VERSION 5.7 ;
  NOWIREEXTENSIONATPIN ON ;
  DIVIDERCHAR "/" ;
  BUSBITCHARS "[]" ;
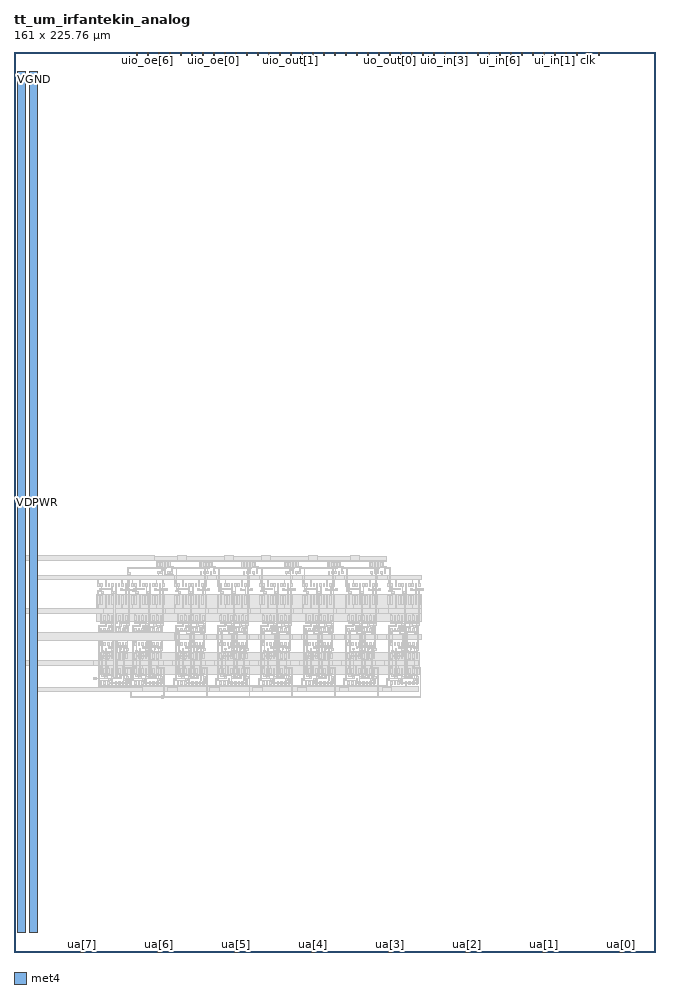
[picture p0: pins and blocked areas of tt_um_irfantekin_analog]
MACRO tt_um_irfantekin_analog
  CLASS BLOCK ;
  FOREIGN tt_um_irfantekin_analog ;
  ORIGIN 0.000 0.000 ;
  SIZE 161.000 BY 225.760 ;
  PIN clk
    DIRECTION INPUT ;
    USE SIGNAL ;
    PORT
      LAYER met4 ;
        RECT 143.830 224.760 144.130 225.760 ;
    END
  END clk
  PIN ena
    DIRECTION INPUT ;
    USE SIGNAL ;
    PORT
      LAYER met4 ;
        RECT 146.590 224.760 146.890 225.760 ;
    END
  END ena
  PIN rst_n
    DIRECTION INPUT ;
    USE SIGNAL ;
    PORT
      LAYER met4 ;
        RECT 141.070 224.760 141.370 225.760 ;
    END
  END rst_n
  PIN ua[0]
    DIRECTION INOUT ;
    USE SIGNAL ;
    PORT
      LAYER met4 ;
        RECT 151.810 0.000 152.710 1.000 ;
    END
  END ua[0]
  PIN ua[1]
    DIRECTION INOUT ;
    USE SIGNAL ;
    PORT
      LAYER met4 ;
        RECT 132.490 0.000 133.390 1.000 ;
    END
  END ua[1]
  PIN ua[2]
    DIRECTION INOUT ;
    USE SIGNAL ;
    PORT
      LAYER met4 ;
        RECT 113.170 0.000 114.070 1.000 ;
    END
  END ua[2]
  PIN ua[3]
    DIRECTION INOUT ;
    USE SIGNAL ;
    PORT
      LAYER met4 ;
        RECT 93.850 0.000 94.750 1.000 ;
    END
  END ua[3]
  PIN ua[4]
    DIRECTION INOUT ;
    USE SIGNAL ;
    PORT
      LAYER met4 ;
        RECT 74.530 0.000 75.430 1.000 ;
    END
  END ua[4]
  PIN ua[5]
    DIRECTION INOUT ;
    USE SIGNAL ;
    PORT
      LAYER met4 ;
        RECT 55.210 0.000 56.110 1.000 ;
    END
  END ua[5]
  PIN ua[6]
    DIRECTION INOUT ;
    USE SIGNAL ;
    PORT
      LAYER met4 ;
        RECT 35.890 0.000 36.790 1.000 ;
    END
  END ua[6]
  PIN ua[7]
    DIRECTION INOUT ;
    USE SIGNAL ;
    PORT
      LAYER met4 ;
        RECT 16.570 0.000 17.470 1.000 ;
    END
  END ua[7]
  PIN ui_in[0]
    DIRECTION INPUT ;
    USE SIGNAL ;
    PORT
      LAYER met4 ;
        RECT 138.310 224.760 138.610 225.760 ;
    END
  END ui_in[0]
  PIN ui_in[1]
    DIRECTION INPUT ;
    USE SIGNAL ;
    PORT
      LAYER met4 ;
        RECT 135.550 224.760 135.850 225.760 ;
    END
  END ui_in[1]
  PIN ui_in[2]
    DIRECTION INPUT ;
    USE SIGNAL ;
    PORT
      LAYER met4 ;
        RECT 132.790 224.760 133.090 225.760 ;
    END
  END ui_in[2]
  PIN ui_in[3]
    DIRECTION INPUT ;
    USE SIGNAL ;
    PORT
      LAYER met4 ;
        RECT 130.030 224.760 130.330 225.760 ;
    END
  END ui_in[3]
  PIN ui_in[4]
    DIRECTION INPUT ;
    USE SIGNAL ;
    PORT
      LAYER met4 ;
        RECT 127.270 224.760 127.570 225.760 ;
    END
  END ui_in[4]
  PIN ui_in[5]
    DIRECTION INPUT ;
    USE SIGNAL ;
    PORT
      LAYER met4 ;
        RECT 124.510 224.760 124.810 225.760 ;
    END
  END ui_in[5]
  PIN ui_in[6]
    DIRECTION INPUT ;
    USE SIGNAL ;
    PORT
      LAYER met4 ;
        RECT 121.750 224.760 122.050 225.760 ;
    END
  END ui_in[6]
  PIN ui_in[7]
    DIRECTION INPUT ;
    USE SIGNAL ;
    PORT
      LAYER met4 ;
        RECT 118.990 224.760 119.290 225.760 ;
    END
  END ui_in[7]
  PIN uio_in[0]
    DIRECTION INPUT ;
    USE SIGNAL ;
    PORT
      LAYER met4 ;
        RECT 116.230 224.760 116.530 225.760 ;
    END
  END uio_in[0]
  PIN uio_in[1]
    DIRECTION INPUT ;
    USE SIGNAL ;
    PORT
      LAYER met4 ;
        RECT 113.470 224.760 113.770 225.760 ;
    END
  END uio_in[1]
  PIN uio_in[2]
    DIRECTION INPUT ;
    USE SIGNAL ;
    PORT
      LAYER met4 ;
        RECT 110.710 224.760 111.010 225.760 ;
    END
  END uio_in[2]
  PIN uio_in[3]
    DIRECTION INPUT ;
    USE SIGNAL ;
    PORT
      LAYER met4 ;
        RECT 107.950 224.760 108.250 225.760 ;
    END
  END uio_in[3]
  PIN uio_in[4]
    DIRECTION INPUT ;
    USE SIGNAL ;
    PORT
      LAYER met4 ;
        RECT 105.190 224.760 105.490 225.760 ;
    END
  END uio_in[4]
  PIN uio_in[5]
    DIRECTION INPUT ;
    USE SIGNAL ;
    PORT
      LAYER met4 ;
        RECT 102.430 224.760 102.730 225.760 ;
    END
  END uio_in[5]
  PIN uio_in[6]
    DIRECTION INPUT ;
    USE SIGNAL ;
    PORT
      LAYER met4 ;
        RECT 99.670 224.760 99.970 225.760 ;
    END
  END uio_in[6]
  PIN uio_in[7]
    DIRECTION INPUT ;
    USE SIGNAL ;
    PORT
      LAYER met4 ;
        RECT 96.910 224.760 97.210 225.760 ;
    END
  END uio_in[7]
  PIN uio_oe[0]
    DIRECTION OUTPUT ;
    USE SIGNAL ;
    PORT
      LAYER met4 ;
        RECT 49.990 224.760 50.290 225.760 ;
    END
  END uio_oe[0]
  PIN uio_oe[1]
    DIRECTION OUTPUT ;
    USE SIGNAL ;
    PORT
      LAYER met4 ;
        RECT 47.230 224.760 47.530 225.760 ;
    END
  END uio_oe[1]
  PIN uio_oe[2]
    DIRECTION OUTPUT ;
    USE SIGNAL ;
    PORT
      LAYER met4 ;
        RECT 44.470 224.760 44.770 225.760 ;
    END
  END uio_oe[2]
  PIN uio_oe[3]
    DIRECTION OUTPUT ;
    USE SIGNAL ;
    PORT
      LAYER met4 ;
        RECT 41.710 224.760 42.010 225.760 ;
    END
  END uio_oe[3]
  PIN uio_oe[4]
    DIRECTION OUTPUT ;
    USE SIGNAL ;
    PORT
      LAYER met4 ;
        RECT 38.950 224.760 39.250 225.760 ;
    END
  END uio_oe[4]
  PIN uio_oe[5]
    DIRECTION OUTPUT ;
    USE SIGNAL ;
    PORT
      LAYER met4 ;
        RECT 36.190 224.760 36.490 225.760 ;
    END
  END uio_oe[5]
  PIN uio_oe[6]
    DIRECTION OUTPUT ;
    USE SIGNAL ;
    PORT
      LAYER met4 ;
        RECT 33.430 224.760 33.730 225.760 ;
    END
  END uio_oe[6]
  PIN uio_oe[7]
    DIRECTION OUTPUT ;
    USE SIGNAL ;
    PORT
      LAYER met4 ;
        RECT 30.670 224.760 30.970 225.760 ;
    END
  END uio_oe[7]
  PIN uio_out[0]
    DIRECTION OUTPUT ;
    USE SIGNAL ;
    PORT
      LAYER met4 ;
        RECT 72.070 224.760 72.370 225.760 ;
    END
  END uio_out[0]
  PIN uio_out[1]
    DIRECTION OUTPUT ;
    USE SIGNAL ;
    PORT
      LAYER met4 ;
        RECT 69.310 224.760 69.610 225.760 ;
    END
  END uio_out[1]
  PIN uio_out[2]
    DIRECTION OUTPUT ;
    USE SIGNAL ;
    PORT
      LAYER met4 ;
        RECT 66.550 224.760 66.850 225.760 ;
    END
  END uio_out[2]
  PIN uio_out[3]
    DIRECTION OUTPUT ;
    USE SIGNAL ;
    PORT
      LAYER met4 ;
        RECT 63.790 224.760 64.090 225.760 ;
    END
  END uio_out[3]
  PIN uio_out[4]
    DIRECTION OUTPUT ;
    USE SIGNAL ;
    PORT
      LAYER met4 ;
        RECT 61.030 224.760 61.330 225.760 ;
    END
  END uio_out[4]
  PIN uio_out[5]
    DIRECTION OUTPUT ;
    USE SIGNAL ;
    PORT
      LAYER met4 ;
        RECT 58.270 224.760 58.570 225.760 ;
    END
  END uio_out[5]
  PIN uio_out[6]
    DIRECTION OUTPUT ;
    USE SIGNAL ;
    PORT
      LAYER met4 ;
        RECT 55.510 224.760 55.810 225.760 ;
    END
  END uio_out[6]
  PIN uio_out[7]
    DIRECTION OUTPUT ;
    USE SIGNAL ;
    PORT
      LAYER met4 ;
        RECT 52.750 224.760 53.050 225.760 ;
    END
  END uio_out[7]
  PIN uo_out[0]
    DIRECTION OUTPUT ;
    USE SIGNAL ;
    PORT
      LAYER met4 ;
        RECT 94.150 224.760 94.450 225.760 ;
    END
  END uo_out[0]
  PIN uo_out[1]
    DIRECTION OUTPUT ;
    USE SIGNAL ;
    PORT
      LAYER met4 ;
        RECT 91.390 224.760 91.690 225.760 ;
    END
  END uo_out[1]
  PIN uo_out[2]
    DIRECTION OUTPUT ;
    USE SIGNAL ;
    PORT
      LAYER met4 ;
        RECT 88.630 224.760 88.930 225.760 ;
    END
  END uo_out[2]
  PIN uo_out[3]
    DIRECTION OUTPUT ;
    USE SIGNAL ;
    PORT
      LAYER met4 ;
        RECT 85.870 224.760 86.170 225.760 ;
    END
  END uo_out[3]
  PIN uo_out[4]
    DIRECTION OUTPUT ;
    USE SIGNAL ;
    PORT
      LAYER met4 ;
        RECT 83.110 224.760 83.410 225.760 ;
    END
  END uo_out[4]
  PIN uo_out[5]
    DIRECTION OUTPUT ;
    USE SIGNAL ;
    PORT
      LAYER met4 ;
        RECT 80.350 224.760 80.650 225.760 ;
    END
  END uo_out[5]
  PIN uo_out[6]
    DIRECTION OUTPUT ;
    USE SIGNAL ;
    PORT
      LAYER met4 ;
        RECT 77.590 224.760 77.890 225.760 ;
    END
  END uo_out[6]
  PIN uo_out[7]
    DIRECTION OUTPUT ;
    USE SIGNAL ;
    PORT
      LAYER met4 ;
        RECT 74.830 224.760 75.130 225.760 ;
    END
  END uo_out[7]
  PIN VDPWR
    DIRECTION INOUT ;
    USE POWER ;
    PORT
      LAYER met4 ;
        RECT 1.000 5.000 3.000 220.760 ;
    END
  END VDPWR
  PIN VGND
    DIRECTION INOUT ;
    USE GROUND ;
    PORT
      LAYER met4 ;
        RECT 4.000 5.000 6.000 220.760 ;
    END
  END VGND
  OBS
      LAYER nwell ;
        RECT 35.750 98.000 93.350 99.300 ;
        RECT 35.750 96.500 39.150 98.000 ;
        RECT 46.450 96.500 49.850 98.000 ;
        RECT 57.150 96.500 60.550 98.000 ;
        RECT 67.850 96.500 71.250 98.000 ;
        RECT 78.550 96.500 81.950 98.000 ;
        RECT 89.250 96.500 92.650 98.000 ;
        RECT 20.650 82.800 102.150 89.700 ;
        RECT 21.150 69.600 101.650 75.200 ;
      LAYER li1 ;
        RECT 32.650 99.300 34.950 99.400 ;
        RECT 41.050 99.300 43.350 99.400 ;
        RECT 52.750 99.300 55.050 99.400 ;
        RECT 62.150 99.300 64.450 99.400 ;
        RECT 73.950 99.300 76.250 99.400 ;
        RECT 84.450 99.300 86.750 99.400 ;
        RECT 31.950 98.200 93.350 99.300 ;
        RECT 36.150 97.800 36.350 98.200 ;
        RECT 37.750 97.800 37.950 98.200 ;
        RECT 46.850 97.800 47.050 98.200 ;
        RECT 48.450 97.800 48.650 98.200 ;
        RECT 57.550 97.800 57.750 98.200 ;
        RECT 59.150 97.800 59.350 98.200 ;
        RECT 68.250 97.800 68.450 98.200 ;
        RECT 69.850 97.800 70.050 98.200 ;
        RECT 78.950 97.800 79.150 98.200 ;
        RECT 80.550 97.800 80.750 98.200 ;
        RECT 89.650 97.800 89.850 98.200 ;
        RECT 91.250 97.800 91.450 98.200 ;
        RECT 36.050 96.800 36.450 97.800 ;
        RECT 36.850 96.800 37.250 97.800 ;
        RECT 37.650 96.800 38.050 97.800 ;
        RECT 38.450 96.800 38.850 97.800 ;
        RECT 46.750 96.800 47.150 97.800 ;
        RECT 47.550 96.800 47.950 97.800 ;
        RECT 48.350 96.800 48.750 97.800 ;
        RECT 49.150 96.800 49.550 97.800 ;
        RECT 57.450 96.800 57.850 97.800 ;
        RECT 58.250 96.800 58.650 97.800 ;
        RECT 59.050 96.800 59.450 97.800 ;
        RECT 59.850 96.800 60.250 97.800 ;
        RECT 68.150 96.800 68.550 97.800 ;
        RECT 68.950 96.800 69.350 97.800 ;
        RECT 69.750 96.800 70.150 97.800 ;
        RECT 70.550 96.800 70.950 97.800 ;
        RECT 78.850 96.800 79.250 97.800 ;
        RECT 79.650 96.800 80.050 97.800 ;
        RECT 80.450 96.800 80.850 97.800 ;
        RECT 81.250 96.800 81.650 97.800 ;
        RECT 89.550 96.800 89.950 97.800 ;
        RECT 90.350 96.800 90.750 97.800 ;
        RECT 91.150 96.800 91.550 97.800 ;
        RECT 91.950 96.800 92.350 97.800 ;
        RECT 36.250 96.100 36.650 96.500 ;
        RECT 36.950 96.400 37.150 96.800 ;
        RECT 38.550 96.600 38.750 96.800 ;
        RECT 37.850 96.400 38.250 96.500 ;
        RECT 38.550 96.400 39.950 96.600 ;
        RECT 36.950 96.200 38.250 96.400 ;
        RECT 37.750 96.100 38.250 96.200 ;
        RECT 39.450 96.100 39.950 96.400 ;
        RECT 46.950 96.100 47.350 96.500 ;
        RECT 47.650 96.400 47.850 96.800 ;
        RECT 49.250 96.600 49.450 96.800 ;
        RECT 48.550 96.400 48.950 96.500 ;
        RECT 49.250 96.400 50.650 96.600 ;
        RECT 47.650 96.200 48.950 96.400 ;
        RECT 48.450 96.100 48.950 96.200 ;
        RECT 50.150 96.100 50.650 96.400 ;
        RECT 57.650 96.100 58.050 96.500 ;
        RECT 58.350 96.400 58.550 96.800 ;
        RECT 59.950 96.600 60.150 96.800 ;
        RECT 59.250 96.400 59.650 96.500 ;
        RECT 59.950 96.400 61.350 96.600 ;
        RECT 58.350 96.200 59.650 96.400 ;
        RECT 59.150 96.100 59.650 96.200 ;
        RECT 60.850 96.100 61.350 96.400 ;
        RECT 68.350 96.100 68.750 96.500 ;
        RECT 69.050 96.400 69.250 96.800 ;
        RECT 70.650 96.600 70.850 96.800 ;
        RECT 69.950 96.400 70.350 96.500 ;
        RECT 70.650 96.400 72.050 96.600 ;
        RECT 69.050 96.200 70.350 96.400 ;
        RECT 69.850 96.100 70.350 96.200 ;
        RECT 71.550 96.100 72.050 96.400 ;
        RECT 79.050 96.100 79.450 96.500 ;
        RECT 79.750 96.400 79.950 96.800 ;
        RECT 81.350 96.600 81.550 96.800 ;
        RECT 80.650 96.400 81.050 96.500 ;
        RECT 81.350 96.400 82.750 96.600 ;
        RECT 79.750 96.200 81.050 96.400 ;
        RECT 80.550 96.100 81.050 96.200 ;
        RECT 82.250 96.100 82.750 96.400 ;
        RECT 89.750 96.100 90.150 96.500 ;
        RECT 90.450 96.400 90.650 96.800 ;
        RECT 92.050 96.600 92.250 96.800 ;
        RECT 91.350 96.400 91.750 96.500 ;
        RECT 92.050 96.400 93.450 96.600 ;
        RECT 90.450 96.200 91.750 96.400 ;
        RECT 91.250 96.100 91.750 96.200 ;
        RECT 92.950 96.100 93.450 96.400 ;
        RECT 37.050 95.600 37.450 96.000 ;
        RECT 37.750 95.400 37.950 96.100 ;
        RECT 39.450 95.400 39.650 96.100 ;
        RECT 47.750 95.600 48.150 96.000 ;
        RECT 48.450 95.400 48.650 96.100 ;
        RECT 50.150 95.400 50.350 96.100 ;
        RECT 58.450 95.600 58.850 96.000 ;
        RECT 59.150 95.400 59.350 96.100 ;
        RECT 60.850 95.400 61.050 96.100 ;
        RECT 69.150 95.600 69.550 96.000 ;
        RECT 69.850 95.400 70.050 96.100 ;
        RECT 71.550 95.400 71.750 96.100 ;
        RECT 79.850 95.600 80.250 96.000 ;
        RECT 80.550 95.400 80.750 96.100 ;
        RECT 82.250 95.400 82.450 96.100 ;
        RECT 90.550 95.600 90.950 96.000 ;
        RECT 91.250 95.400 91.450 96.100 ;
        RECT 92.950 95.400 93.150 96.100 ;
        RECT 36.050 94.900 36.450 95.400 ;
        RECT 36.850 94.900 37.250 95.400 ;
        RECT 37.650 94.900 38.050 95.400 ;
        RECT 38.550 94.900 38.950 95.400 ;
        RECT 39.350 94.900 39.750 95.400 ;
        RECT 46.750 94.900 47.150 95.400 ;
        RECT 47.550 94.900 47.950 95.400 ;
        RECT 48.350 94.900 48.750 95.400 ;
        RECT 49.250 94.900 49.650 95.400 ;
        RECT 50.050 94.900 50.450 95.400 ;
        RECT 57.450 94.900 57.850 95.400 ;
        RECT 58.250 94.900 58.650 95.400 ;
        RECT 59.050 94.900 59.450 95.400 ;
        RECT 59.950 94.900 60.350 95.400 ;
        RECT 60.750 94.900 61.150 95.400 ;
        RECT 68.150 94.900 68.550 95.400 ;
        RECT 68.950 94.900 69.350 95.400 ;
        RECT 69.750 94.900 70.150 95.400 ;
        RECT 70.650 94.900 71.050 95.400 ;
        RECT 71.450 94.900 71.850 95.400 ;
        RECT 78.850 94.900 79.250 95.400 ;
        RECT 79.650 94.900 80.050 95.400 ;
        RECT 80.450 94.900 80.850 95.400 ;
        RECT 81.350 94.900 81.750 95.400 ;
        RECT 82.150 94.900 82.550 95.400 ;
        RECT 89.550 94.900 89.950 95.400 ;
        RECT 90.350 94.900 90.750 95.400 ;
        RECT 91.150 94.900 91.550 95.400 ;
        RECT 92.050 94.900 92.450 95.400 ;
        RECT 92.850 94.900 93.250 95.400 ;
        RECT 36.150 94.500 36.350 94.900 ;
        RECT 38.650 94.500 38.850 94.900 ;
        RECT 46.850 94.500 47.050 94.900 ;
        RECT 49.350 94.500 49.550 94.900 ;
        RECT 57.550 94.500 57.750 94.900 ;
        RECT 60.050 94.500 60.250 94.900 ;
        RECT 68.250 94.500 68.450 94.900 ;
        RECT 70.750 94.500 70.950 94.900 ;
        RECT 78.950 94.500 79.150 94.900 ;
        RECT 81.450 94.500 81.650 94.900 ;
        RECT 89.650 94.500 89.850 94.900 ;
        RECT 92.150 94.500 92.350 94.900 ;
        RECT 20.650 93.400 102.150 94.500 ;
        RECT 21.050 92.400 21.250 93.400 ;
        RECT 22.950 92.400 23.150 93.400 ;
        RECT 27.050 92.400 27.250 93.400 ;
        RECT 28.750 92.400 28.950 93.400 ;
        RECT 29.650 92.400 29.850 93.400 ;
        RECT 31.550 92.400 31.750 93.400 ;
        RECT 35.650 92.400 35.850 93.400 ;
        RECT 37.350 92.400 37.550 93.400 ;
        RECT 40.350 92.400 40.550 93.400 ;
        RECT 42.250 92.400 42.450 93.400 ;
        RECT 46.350 92.400 46.550 93.400 ;
        RECT 48.050 92.400 48.250 93.400 ;
        RECT 51.050 92.400 51.250 93.400 ;
        RECT 52.950 92.400 53.150 93.400 ;
        RECT 57.050 92.400 57.250 93.400 ;
        RECT 58.750 92.400 58.950 93.400 ;
        RECT 61.750 92.400 61.950 93.400 ;
        RECT 63.650 92.400 63.850 93.400 ;
        RECT 67.750 92.400 67.950 93.400 ;
        RECT 69.450 92.400 69.650 93.400 ;
        RECT 72.450 92.400 72.650 93.400 ;
        RECT 74.350 92.400 74.550 93.400 ;
        RECT 78.450 92.400 78.650 93.400 ;
        RECT 80.150 92.400 80.350 93.400 ;
        RECT 83.150 92.400 83.350 93.400 ;
        RECT 85.050 92.400 85.250 93.400 ;
        RECT 89.150 92.400 89.350 93.400 ;
        RECT 90.850 92.400 91.050 93.400 ;
        RECT 93.850 92.400 94.050 93.400 ;
        RECT 95.750 92.400 95.950 93.400 ;
        RECT 99.850 92.400 100.050 93.400 ;
        RECT 101.550 92.400 101.750 93.400 ;
        RECT 20.950 91.600 21.350 92.400 ;
        RECT 21.750 91.600 22.150 92.400 ;
        RECT 22.850 91.600 23.250 92.400 ;
        RECT 23.650 91.600 24.050 92.400 ;
        RECT 24.450 91.600 24.850 92.400 ;
        RECT 25.350 91.600 25.750 92.400 ;
        RECT 26.150 91.600 26.550 92.400 ;
        RECT 26.950 91.600 27.350 92.400 ;
        RECT 27.850 91.600 28.250 92.400 ;
        RECT 28.650 91.600 29.050 92.400 ;
        RECT 29.550 91.600 29.950 92.400 ;
        RECT 30.350 91.600 30.750 92.400 ;
        RECT 31.450 91.600 31.850 92.400 ;
        RECT 32.250 91.600 32.650 92.400 ;
        RECT 33.050 91.600 33.450 92.400 ;
        RECT 33.950 91.600 34.350 92.400 ;
        RECT 34.750 91.600 35.150 92.400 ;
        RECT 35.550 91.600 35.950 92.400 ;
        RECT 36.450 91.600 36.850 92.400 ;
        RECT 37.250 91.600 37.650 92.400 ;
        RECT 40.250 91.600 40.650 92.400 ;
        RECT 41.050 91.600 41.450 92.400 ;
        RECT 42.150 91.600 42.550 92.400 ;
        RECT 42.950 91.600 43.350 92.400 ;
        RECT 43.750 91.600 44.150 92.400 ;
        RECT 44.650 91.600 45.050 92.400 ;
        RECT 45.450 91.600 45.850 92.400 ;
        RECT 46.250 91.600 46.650 92.400 ;
        RECT 47.150 91.600 47.550 92.400 ;
        RECT 47.950 91.600 48.350 92.400 ;
        RECT 50.950 91.600 51.350 92.400 ;
        RECT 51.750 91.600 52.150 92.400 ;
        RECT 52.850 91.600 53.250 92.400 ;
        RECT 53.650 91.600 54.050 92.400 ;
        RECT 54.450 91.600 54.850 92.400 ;
        RECT 55.350 91.600 55.750 92.400 ;
        RECT 56.150 91.600 56.550 92.400 ;
        RECT 56.950 91.600 57.350 92.400 ;
        RECT 57.850 91.600 58.250 92.400 ;
        RECT 58.650 91.600 59.050 92.400 ;
        RECT 61.650 91.600 62.050 92.400 ;
        RECT 62.450 91.600 62.850 92.400 ;
        RECT 63.550 91.600 63.950 92.400 ;
        RECT 64.350 91.600 64.750 92.400 ;
        RECT 65.150 91.600 65.550 92.400 ;
        RECT 66.050 91.600 66.450 92.400 ;
        RECT 66.850 91.600 67.250 92.400 ;
        RECT 67.650 91.600 68.050 92.400 ;
        RECT 68.550 91.600 68.950 92.400 ;
        RECT 69.350 91.600 69.750 92.400 ;
        RECT 72.350 91.600 72.750 92.400 ;
        RECT 73.150 91.600 73.550 92.400 ;
        RECT 74.250 91.600 74.650 92.400 ;
        RECT 75.050 91.600 75.450 92.400 ;
        RECT 75.850 91.600 76.250 92.400 ;
        RECT 76.750 91.600 77.150 92.400 ;
        RECT 77.550 91.600 77.950 92.400 ;
        RECT 78.350 91.600 78.750 92.400 ;
        RECT 79.250 91.600 79.650 92.400 ;
        RECT 80.050 91.600 80.450 92.400 ;
        RECT 83.050 91.600 83.450 92.400 ;
        RECT 83.850 91.600 84.250 92.400 ;
        RECT 84.950 91.600 85.350 92.400 ;
        RECT 85.750 91.600 86.150 92.400 ;
        RECT 86.550 91.600 86.950 92.400 ;
        RECT 87.450 91.600 87.850 92.400 ;
        RECT 88.250 91.600 88.650 92.400 ;
        RECT 89.050 91.600 89.450 92.400 ;
        RECT 89.950 91.600 90.350 92.400 ;
        RECT 90.750 91.600 91.150 92.400 ;
        RECT 93.750 91.600 94.150 92.400 ;
        RECT 94.550 91.600 94.950 92.400 ;
        RECT 95.650 91.600 96.050 92.400 ;
        RECT 96.450 91.600 96.850 92.400 ;
        RECT 97.250 91.600 97.650 92.400 ;
        RECT 98.150 91.600 98.550 92.400 ;
        RECT 98.950 91.600 99.350 92.400 ;
        RECT 99.750 91.600 100.150 92.400 ;
        RECT 100.650 91.600 101.050 92.400 ;
        RECT 101.450 91.600 101.850 92.400 ;
        RECT 21.250 90.700 21.650 90.800 ;
        RECT 21.050 90.400 21.650 90.700 ;
        RECT 21.850 90.400 22.050 91.600 ;
        RECT 23.850 90.900 24.250 91.300 ;
        RECT 24.550 90.500 24.750 91.600 ;
        RECT 25.450 90.500 25.650 91.600 ;
        RECT 26.750 91.000 27.150 91.100 ;
        RECT 27.950 91.000 28.150 91.600 ;
        RECT 26.750 90.800 28.150 91.000 ;
        RECT 26.750 90.700 27.150 90.800 ;
        RECT 21.050 89.400 21.250 90.400 ;
        RECT 21.850 90.000 22.550 90.400 ;
        RECT 21.850 89.400 22.050 90.000 ;
        RECT 24.550 89.900 25.650 90.500 ;
        RECT 24.550 89.400 24.750 89.900 ;
        RECT 25.450 89.400 25.650 89.900 ;
        RECT 27.950 89.400 28.150 90.800 ;
        RECT 28.450 90.700 28.850 91.100 ;
        RECT 29.850 90.400 30.250 90.800 ;
        RECT 30.450 90.400 30.650 91.600 ;
        RECT 32.450 90.900 32.850 91.300 ;
        RECT 33.150 90.500 33.350 91.600 ;
        RECT 34.050 90.500 34.250 91.600 ;
        RECT 35.350 91.000 35.750 91.100 ;
        RECT 36.550 91.000 36.750 91.600 ;
        RECT 35.350 90.800 36.750 91.000 ;
        RECT 35.350 90.700 35.750 90.800 ;
        RECT 30.450 90.000 31.150 90.400 ;
        RECT 30.450 89.400 30.650 90.000 ;
        RECT 33.150 89.900 34.250 90.500 ;
        RECT 33.150 89.400 33.350 89.900 ;
        RECT 34.050 89.400 34.250 89.900 ;
        RECT 36.550 89.400 36.750 90.800 ;
        RECT 37.050 90.700 37.450 91.100 ;
        RECT 40.550 90.400 40.950 90.800 ;
        RECT 41.150 90.400 41.350 91.600 ;
        RECT 43.150 90.900 43.550 91.300 ;
        RECT 43.850 90.500 44.050 91.600 ;
        RECT 44.750 90.500 44.950 91.600 ;
        RECT 46.050 91.000 46.450 91.100 ;
        RECT 47.250 91.000 47.450 91.600 ;
        RECT 46.050 90.800 47.450 91.000 ;
        RECT 46.050 90.700 46.450 90.800 ;
        RECT 41.150 90.000 41.850 90.400 ;
        RECT 41.150 89.400 41.350 90.000 ;
        RECT 43.850 89.900 44.950 90.500 ;
        RECT 43.850 89.400 44.050 89.900 ;
        RECT 44.750 89.400 44.950 89.900 ;
        RECT 47.250 89.400 47.450 90.800 ;
        RECT 47.750 90.700 48.150 91.100 ;
        RECT 51.250 90.400 51.650 90.800 ;
        RECT 51.850 90.400 52.050 91.600 ;
        RECT 53.850 90.900 54.250 91.300 ;
        RECT 54.550 90.500 54.750 91.600 ;
        RECT 55.450 90.500 55.650 91.600 ;
        RECT 56.750 91.000 57.150 91.100 ;
        RECT 57.950 91.000 58.150 91.600 ;
        RECT 56.750 90.800 58.150 91.000 ;
        RECT 56.750 90.700 57.150 90.800 ;
        RECT 51.850 90.000 52.550 90.400 ;
        RECT 51.850 89.400 52.050 90.000 ;
        RECT 54.550 89.900 55.650 90.500 ;
        RECT 54.550 89.400 54.750 89.900 ;
        RECT 55.450 89.400 55.650 89.900 ;
        RECT 57.950 89.400 58.150 90.800 ;
        RECT 58.450 90.700 58.850 91.100 ;
        RECT 61.950 90.400 62.350 90.800 ;
        RECT 62.550 90.400 62.750 91.600 ;
        RECT 64.550 90.900 64.950 91.300 ;
        RECT 65.250 90.500 65.450 91.600 ;
        RECT 66.150 90.500 66.350 91.600 ;
        RECT 67.450 91.000 67.850 91.100 ;
        RECT 68.650 91.000 68.850 91.600 ;
        RECT 67.450 90.800 68.850 91.000 ;
        RECT 67.450 90.700 67.850 90.800 ;
        RECT 62.550 90.000 63.250 90.400 ;
        RECT 62.550 89.400 62.750 90.000 ;
        RECT 65.250 89.900 66.350 90.500 ;
        RECT 65.250 89.400 65.450 89.900 ;
        RECT 66.150 89.400 66.350 89.900 ;
        RECT 68.650 89.400 68.850 90.800 ;
        RECT 69.150 90.700 69.550 91.100 ;
        RECT 72.650 90.400 73.050 90.800 ;
        RECT 73.250 90.400 73.450 91.600 ;
        RECT 75.250 90.900 75.650 91.300 ;
        RECT 75.950 90.500 76.150 91.600 ;
        RECT 76.850 90.500 77.050 91.600 ;
        RECT 78.150 91.000 78.550 91.100 ;
        RECT 79.350 91.000 79.550 91.600 ;
        RECT 78.150 90.800 79.550 91.000 ;
        RECT 78.150 90.700 78.550 90.800 ;
        RECT 73.250 90.000 73.950 90.400 ;
        RECT 73.250 89.400 73.450 90.000 ;
        RECT 75.950 89.900 77.050 90.500 ;
        RECT 75.950 89.400 76.150 89.900 ;
        RECT 76.850 89.400 77.050 89.900 ;
        RECT 79.350 89.400 79.550 90.800 ;
        RECT 79.850 90.700 80.250 91.100 ;
        RECT 83.350 90.400 83.750 90.800 ;
        RECT 83.950 90.400 84.150 91.600 ;
        RECT 85.950 90.900 86.350 91.300 ;
        RECT 86.650 90.500 86.850 91.600 ;
        RECT 87.550 90.500 87.750 91.600 ;
        RECT 88.850 91.000 89.250 91.100 ;
        RECT 90.050 91.000 90.250 91.600 ;
        RECT 88.850 90.800 90.250 91.000 ;
        RECT 88.850 90.700 89.250 90.800 ;
        RECT 83.950 90.000 84.650 90.400 ;
        RECT 83.950 89.400 84.150 90.000 ;
        RECT 86.650 89.900 87.750 90.500 ;
        RECT 86.650 89.400 86.850 89.900 ;
        RECT 87.550 89.400 87.750 89.900 ;
        RECT 90.050 89.400 90.250 90.800 ;
        RECT 90.550 90.700 90.950 91.100 ;
        RECT 94.050 90.400 94.450 90.800 ;
        RECT 94.650 90.400 94.850 91.600 ;
        RECT 96.650 90.900 97.050 91.300 ;
        RECT 97.350 90.500 97.550 91.600 ;
        RECT 98.250 90.500 98.450 91.600 ;
        RECT 99.550 91.000 99.950 91.100 ;
        RECT 100.750 91.000 100.950 91.600 ;
        RECT 99.550 90.800 100.950 91.000 ;
        RECT 99.550 90.700 99.950 90.800 ;
        RECT 94.650 90.000 95.350 90.400 ;
        RECT 94.650 89.400 94.850 90.000 ;
        RECT 97.350 89.900 98.450 90.500 ;
        RECT 97.350 89.400 97.550 89.900 ;
        RECT 98.250 89.400 98.450 89.900 ;
        RECT 100.750 89.400 100.950 90.800 ;
        RECT 101.250 90.700 101.650 91.100 ;
        RECT 20.950 87.100 21.350 89.400 ;
        RECT 21.750 87.100 22.150 89.400 ;
        RECT 22.850 87.100 23.250 89.400 ;
        RECT 23.650 87.100 24.050 89.400 ;
        RECT 24.450 87.100 24.850 89.400 ;
        RECT 25.350 87.100 25.750 89.400 ;
        RECT 26.150 87.100 26.550 89.400 ;
        RECT 26.950 87.100 27.350 89.400 ;
        RECT 27.850 87.100 28.250 89.400 ;
        RECT 28.650 87.100 29.050 89.400 ;
        RECT 29.550 87.100 29.950 89.400 ;
        RECT 30.350 87.100 30.750 89.400 ;
        RECT 31.450 87.100 31.850 89.400 ;
        RECT 32.250 87.100 32.650 89.400 ;
        RECT 33.050 87.100 33.450 89.400 ;
        RECT 33.950 87.100 34.350 89.400 ;
        RECT 34.750 87.100 35.150 89.400 ;
        RECT 35.550 87.100 35.950 89.400 ;
        RECT 36.450 87.100 36.850 89.400 ;
        RECT 37.250 87.100 37.650 89.400 ;
        RECT 40.250 87.100 40.650 89.400 ;
        RECT 41.050 87.100 41.450 89.400 ;
        RECT 42.150 87.100 42.550 89.400 ;
        RECT 42.950 87.100 43.350 89.400 ;
        RECT 43.750 87.100 44.150 89.400 ;
        RECT 44.650 87.100 45.050 89.400 ;
        RECT 45.450 87.100 45.850 89.400 ;
        RECT 46.250 87.100 46.650 89.400 ;
        RECT 47.150 87.100 47.550 89.400 ;
        RECT 47.950 87.100 48.350 89.400 ;
        RECT 50.950 87.100 51.350 89.400 ;
        RECT 51.750 87.100 52.150 89.400 ;
        RECT 52.850 87.100 53.250 89.400 ;
        RECT 53.650 87.100 54.050 89.400 ;
        RECT 54.450 87.100 54.850 89.400 ;
        RECT 55.350 87.100 55.750 89.400 ;
        RECT 56.150 87.100 56.550 89.400 ;
        RECT 56.950 87.100 57.350 89.400 ;
        RECT 57.850 87.100 58.250 89.400 ;
        RECT 58.650 87.100 59.050 89.400 ;
        RECT 61.650 87.100 62.050 89.400 ;
        RECT 62.450 87.100 62.850 89.400 ;
        RECT 63.550 87.100 63.950 89.400 ;
        RECT 64.350 87.100 64.750 89.400 ;
        RECT 65.150 87.100 65.550 89.400 ;
        RECT 66.050 87.100 66.450 89.400 ;
        RECT 66.850 87.100 67.250 89.400 ;
        RECT 67.650 87.100 68.050 89.400 ;
        RECT 68.550 87.100 68.950 89.400 ;
        RECT 69.350 87.100 69.750 89.400 ;
        RECT 72.350 87.100 72.750 89.400 ;
        RECT 73.150 87.100 73.550 89.400 ;
        RECT 74.250 87.100 74.650 89.400 ;
        RECT 75.050 87.100 75.450 89.400 ;
        RECT 75.850 87.100 76.250 89.400 ;
        RECT 76.750 87.100 77.150 89.400 ;
        RECT 77.550 87.100 77.950 89.400 ;
        RECT 78.350 87.100 78.750 89.400 ;
        RECT 79.250 87.100 79.650 89.400 ;
        RECT 80.050 87.100 80.450 89.400 ;
        RECT 83.050 87.100 83.450 89.400 ;
        RECT 83.850 87.100 84.250 89.400 ;
        RECT 84.950 87.100 85.350 89.400 ;
        RECT 85.750 87.100 86.150 89.400 ;
        RECT 86.550 87.100 86.950 89.400 ;
        RECT 87.450 87.100 87.850 89.400 ;
        RECT 88.250 87.100 88.650 89.400 ;
        RECT 89.050 87.100 89.450 89.400 ;
        RECT 89.950 87.100 90.350 89.400 ;
        RECT 90.750 87.100 91.150 89.400 ;
        RECT 93.750 87.100 94.150 89.400 ;
        RECT 94.550 87.100 94.950 89.400 ;
        RECT 95.650 87.100 96.050 89.400 ;
        RECT 96.450 87.100 96.850 89.400 ;
        RECT 97.250 87.100 97.650 89.400 ;
        RECT 98.150 87.100 98.550 89.400 ;
        RECT 98.950 87.100 99.350 89.400 ;
        RECT 99.750 87.100 100.150 89.400 ;
        RECT 100.650 87.100 101.050 89.400 ;
        RECT 101.450 87.100 101.850 89.400 ;
        RECT 21.050 86.200 21.250 87.100 ;
        RECT 22.950 86.200 23.150 87.100 ;
        RECT 27.050 86.200 27.250 87.100 ;
        RECT 28.750 86.200 28.950 87.100 ;
        RECT 29.650 86.200 29.850 87.100 ;
        RECT 31.550 86.200 31.750 87.100 ;
        RECT 35.650 86.200 35.850 87.100 ;
        RECT 37.350 86.200 37.550 87.100 ;
        RECT 40.350 86.200 40.550 87.100 ;
        RECT 42.250 86.200 42.450 87.100 ;
        RECT 46.350 86.200 46.550 87.100 ;
        RECT 48.050 86.200 48.250 87.100 ;
        RECT 51.050 86.200 51.250 87.100 ;
        RECT 52.950 86.200 53.150 87.100 ;
        RECT 57.050 86.200 57.250 87.100 ;
        RECT 58.750 86.200 58.950 87.100 ;
        RECT 61.750 86.200 61.950 87.100 ;
        RECT 63.650 86.200 63.850 87.100 ;
        RECT 67.750 86.200 67.950 87.100 ;
        RECT 69.450 86.200 69.650 87.100 ;
        RECT 72.450 86.200 72.650 87.100 ;
        RECT 74.350 86.200 74.550 87.100 ;
        RECT 78.450 86.200 78.650 87.100 ;
        RECT 80.150 86.200 80.350 87.100 ;
        RECT 83.150 86.200 83.350 87.100 ;
        RECT 85.050 86.200 85.250 87.100 ;
        RECT 89.150 86.200 89.350 87.100 ;
        RECT 90.850 86.200 91.050 87.100 ;
        RECT 93.850 86.200 94.050 87.100 ;
        RECT 95.750 86.200 95.950 87.100 ;
        RECT 99.850 86.200 100.050 87.100 ;
        RECT 101.550 86.200 101.750 87.100 ;
        RECT 20.650 85.000 102.150 86.200 ;
        RECT 21.750 84.400 21.950 85.000 ;
        RECT 23.550 84.400 23.750 85.000 ;
        RECT 25.450 84.400 25.650 85.000 ;
        RECT 27.250 84.400 27.450 85.000 ;
        RECT 30.350 84.400 30.550 85.000 ;
        RECT 32.150 84.400 32.350 85.000 ;
        RECT 34.050 84.400 34.250 85.000 ;
        RECT 35.850 84.400 36.050 85.000 ;
        RECT 41.050 84.400 41.250 85.000 ;
        RECT 42.850 84.400 43.050 85.000 ;
        RECT 44.750 84.400 44.950 85.000 ;
        RECT 46.550 84.400 46.750 85.000 ;
        RECT 51.750 84.400 51.950 85.000 ;
        RECT 53.550 84.400 53.750 85.000 ;
        RECT 55.450 84.400 55.650 85.000 ;
        RECT 57.250 84.400 57.450 85.000 ;
        RECT 62.450 84.400 62.650 85.000 ;
        RECT 64.250 84.400 64.450 85.000 ;
        RECT 66.150 84.400 66.350 85.000 ;
        RECT 67.950 84.400 68.150 85.000 ;
        RECT 73.150 84.400 73.350 85.000 ;
        RECT 74.950 84.400 75.150 85.000 ;
        RECT 76.850 84.400 77.050 85.000 ;
        RECT 78.650 84.400 78.850 85.000 ;
        RECT 83.850 84.400 84.050 85.000 ;
        RECT 85.650 84.400 85.850 85.000 ;
        RECT 87.550 84.400 87.750 85.000 ;
        RECT 89.350 84.400 89.550 85.000 ;
        RECT 94.550 84.400 94.750 85.000 ;
        RECT 96.350 84.400 96.550 85.000 ;
        RECT 98.250 84.400 98.450 85.000 ;
        RECT 100.050 84.400 100.250 85.000 ;
        RECT 21.650 83.100 22.050 84.400 ;
        RECT 22.550 83.100 22.950 84.400 ;
        RECT 23.450 83.100 23.850 84.400 ;
        RECT 24.350 83.100 24.750 84.400 ;
        RECT 25.350 83.100 25.750 84.400 ;
        RECT 26.250 83.100 26.650 84.400 ;
        RECT 27.150 83.100 27.550 84.400 ;
        RECT 28.050 83.100 28.450 84.400 ;
        RECT 30.250 83.100 30.650 84.400 ;
        RECT 31.150 83.100 31.550 84.400 ;
        RECT 32.050 83.100 32.450 84.400 ;
        RECT 32.950 83.100 33.350 84.400 ;
        RECT 33.950 83.100 34.350 84.400 ;
        RECT 34.850 83.100 35.250 84.400 ;
        RECT 35.750 83.100 36.150 84.400 ;
        RECT 36.650 83.100 37.050 84.400 ;
        RECT 40.950 83.100 41.350 84.400 ;
        RECT 41.850 83.100 42.250 84.400 ;
        RECT 42.750 83.100 43.150 84.400 ;
        RECT 43.650 83.100 44.050 84.400 ;
        RECT 44.650 83.100 45.050 84.400 ;
        RECT 45.550 83.100 45.950 84.400 ;
        RECT 46.450 83.100 46.850 84.400 ;
        RECT 47.350 83.100 47.750 84.400 ;
        RECT 51.650 83.100 52.050 84.400 ;
        RECT 52.550 83.100 52.950 84.400 ;
        RECT 53.450 83.100 53.850 84.400 ;
        RECT 54.350 83.100 54.750 84.400 ;
        RECT 55.350 83.100 55.750 84.400 ;
        RECT 56.250 83.100 56.650 84.400 ;
        RECT 57.150 83.100 57.550 84.400 ;
        RECT 58.050 83.100 58.450 84.400 ;
        RECT 62.350 83.100 62.750 84.400 ;
        RECT 63.250 83.100 63.650 84.400 ;
        RECT 64.150 83.100 64.550 84.400 ;
        RECT 65.050 83.100 65.450 84.400 ;
        RECT 66.050 83.100 66.450 84.400 ;
        RECT 66.950 83.100 67.350 84.400 ;
        RECT 67.850 83.100 68.250 84.400 ;
        RECT 68.750 83.100 69.150 84.400 ;
        RECT 73.050 83.100 73.450 84.400 ;
        RECT 73.950 83.100 74.350 84.400 ;
        RECT 74.850 83.100 75.250 84.400 ;
        RECT 75.750 83.100 76.150 84.400 ;
        RECT 76.750 83.100 77.150 84.400 ;
        RECT 77.650 83.100 78.050 84.400 ;
        RECT 78.550 83.100 78.950 84.400 ;
        RECT 79.450 83.100 79.850 84.400 ;
        RECT 83.750 83.100 84.150 84.400 ;
        RECT 84.650 83.100 85.050 84.400 ;
        RECT 85.550 83.100 85.950 84.400 ;
        RECT 86.450 83.100 86.850 84.400 ;
        RECT 87.450 83.100 87.850 84.400 ;
        RECT 88.350 83.100 88.750 84.400 ;
        RECT 89.250 83.100 89.650 84.400 ;
        RECT 90.150 83.100 90.550 84.400 ;
        RECT 94.450 83.100 94.850 84.400 ;
        RECT 95.350 83.100 95.750 84.400 ;
        RECT 96.250 83.100 96.650 84.400 ;
        RECT 97.150 83.100 97.550 84.400 ;
        RECT 98.150 83.100 98.550 84.400 ;
        RECT 99.050 83.100 99.450 84.400 ;
        RECT 99.950 83.100 100.350 84.400 ;
        RECT 100.850 83.100 101.250 84.400 ;
        RECT 21.750 82.700 21.950 83.100 ;
        RECT 22.650 82.700 22.850 83.100 ;
        RECT 24.450 82.700 24.650 83.100 ;
        RECT 21.750 82.400 22.350 82.700 ;
        RECT 22.650 82.500 24.650 82.700 ;
        RECT 21.950 82.300 22.350 82.400 ;
        RECT 24.450 82.400 24.650 82.500 ;
        RECT 25.450 82.700 25.650 83.100 ;
        RECT 26.350 82.700 26.550 83.100 ;
        RECT 28.150 82.700 28.350 83.100 ;
        RECT 25.450 82.400 26.050 82.700 ;
        RECT 26.350 82.500 28.350 82.700 ;
        RECT 22.850 81.800 23.250 82.200 ;
        RECT 23.650 81.300 24.250 81.900 ;
        RECT 24.450 81.800 25.050 82.400 ;
        RECT 25.650 82.300 26.050 82.400 ;
        RECT 28.150 82.400 28.350 82.500 ;
        RECT 30.350 82.700 30.550 83.100 ;
        RECT 31.250 82.700 31.450 83.100 ;
        RECT 33.050 82.700 33.250 83.100 ;
        RECT 30.350 82.400 30.950 82.700 ;
        RECT 31.250 82.500 33.250 82.700 ;
        RECT 24.450 81.100 24.650 81.800 ;
        RECT 26.450 81.700 27.050 82.300 ;
        RECT 27.350 81.300 27.950 81.900 ;
        RECT 28.150 81.800 28.750 82.400 ;
        RECT 30.550 82.300 30.950 82.400 ;
        RECT 33.050 82.400 33.250 82.500 ;
        RECT 34.050 82.700 34.250 83.100 ;
        RECT 34.950 82.700 35.150 83.100 ;
        RECT 36.750 82.700 36.950 83.100 ;
        RECT 34.050 82.400 34.650 82.700 ;
        RECT 34.950 82.500 36.950 82.700 ;
        RECT 31.450 81.800 31.850 82.200 ;
        RECT 28.150 81.100 28.350 81.800 ;
        RECT 32.250 81.300 32.850 81.900 ;
        RECT 33.050 81.800 33.650 82.400 ;
        RECT 34.250 82.300 34.650 82.400 ;
        RECT 36.750 82.400 36.950 82.500 ;
        RECT 41.050 82.700 41.250 83.100 ;
        RECT 41.950 82.700 42.150 83.100 ;
        RECT 43.750 82.700 43.950 83.100 ;
        RECT 41.050 82.400 41.650 82.700 ;
        RECT 41.950 82.500 43.950 82.700 ;
        RECT 33.050 81.100 33.250 81.800 ;
        RECT 35.050 81.700 35.650 82.300 ;
        RECT 35.950 81.300 36.550 81.900 ;
        RECT 36.750 81.800 37.350 82.400 ;
        RECT 41.250 82.300 41.650 82.400 ;
        RECT 43.750 82.400 43.950 82.500 ;
        RECT 44.750 82.700 44.950 83.100 ;
        RECT 45.650 82.700 45.850 83.100 ;
        RECT 47.450 82.700 47.650 83.100 ;
        RECT 44.750 82.400 45.350 82.700 ;
        RECT 45.650 82.500 47.650 82.700 ;
        RECT 42.150 81.800 42.550 82.200 ;
        RECT 36.750 81.100 36.950 81.800 ;
        RECT 42.950 81.300 43.550 81.900 ;
        RECT 43.750 81.800 44.350 82.400 ;
        RECT 44.950 82.300 45.350 82.400 ;
        RECT 47.450 82.400 47.650 82.500 ;
        RECT 51.750 82.700 51.950 83.100 ;
        RECT 52.650 82.700 52.850 83.100 ;
        RECT 54.450 82.700 54.650 83.100 ;
        RECT 51.750 82.400 52.350 82.700 ;
        RECT 52.650 82.500 54.650 82.700 ;
        RECT 43.750 81.100 43.950 81.800 ;
        RECT 45.750 81.700 46.350 82.300 ;
        RECT 46.650 81.300 47.250 81.900 ;
        RECT 47.450 81.800 48.050 82.400 ;
        RECT 51.950 82.300 52.350 82.400 ;
        RECT 54.450 82.400 54.650 82.500 ;
        RECT 55.450 82.700 55.650 83.100 ;
        RECT 56.350 82.700 56.550 83.100 ;
        RECT 58.150 82.700 58.350 83.100 ;
        RECT 55.450 82.400 56.050 82.700 ;
        RECT 56.350 82.500 58.350 82.700 ;
        RECT 52.850 81.800 53.250 82.200 ;
        RECT 47.450 81.100 47.650 81.800 ;
        RECT 53.650 81.300 54.250 81.900 ;
        RECT 54.450 81.800 55.050 82.400 ;
        RECT 55.650 82.300 56.050 82.400 ;
        RECT 58.150 82.400 58.350 82.500 ;
        RECT 62.450 82.700 62.650 83.100 ;
        RECT 63.350 82.700 63.550 83.100 ;
        RECT 65.150 82.700 65.350 83.100 ;
        RECT 62.450 82.400 63.050 82.700 ;
        RECT 63.350 82.500 65.350 82.700 ;
        RECT 54.450 81.100 54.650 81.800 ;
        RECT 56.450 81.700 57.050 82.300 ;
        RECT 57.350 81.300 57.950 81.900 ;
        RECT 58.150 81.800 58.750 82.400 ;
        RECT 62.650 82.300 63.050 82.400 ;
        RECT 65.150 82.400 65.350 82.500 ;
        RECT 66.150 82.700 66.350 83.100 ;
        RECT 67.050 82.700 67.250 83.100 ;
        RECT 68.850 82.700 69.050 83.100 ;
        RECT 66.150 82.400 66.750 82.700 ;
        RECT 67.050 82.500 69.050 82.700 ;
        RECT 63.550 81.800 63.950 82.200 ;
        RECT 58.150 81.100 58.350 81.800 ;
        RECT 64.350 81.300 64.950 81.900 ;
        RECT 65.150 81.800 65.750 82.400 ;
        RECT 66.350 82.300 66.750 82.400 ;
        RECT 68.850 82.400 69.050 82.500 ;
        RECT 73.150 82.700 73.350 83.100 ;
        RECT 74.050 82.700 74.250 83.100 ;
        RECT 75.850 82.700 76.050 83.100 ;
        RECT 73.150 82.400 73.750 82.700 ;
        RECT 74.050 82.500 76.050 82.700 ;
        RECT 65.150 81.100 65.350 81.800 ;
        RECT 67.150 81.700 67.750 82.300 ;
        RECT 68.050 81.300 68.650 81.900 ;
        RECT 68.850 81.800 69.450 82.400 ;
        RECT 73.350 82.300 73.750 82.400 ;
        RECT 75.850 82.400 76.050 82.500 ;
        RECT 76.850 82.700 77.050 83.100 ;
        RECT 77.750 82.700 77.950 83.100 ;
        RECT 79.550 82.700 79.750 83.100 ;
        RECT 76.850 82.400 77.450 82.700 ;
        RECT 77.750 82.500 79.750 82.700 ;
        RECT 74.250 81.800 74.650 82.200 ;
        RECT 68.850 81.100 69.050 81.800 ;
        RECT 75.050 81.300 75.650 81.900 ;
        RECT 75.850 81.800 76.450 82.400 ;
        RECT 77.050 82.300 77.450 82.400 ;
        RECT 79.550 82.400 79.750 82.500 ;
        RECT 83.850 82.700 84.050 83.100 ;
        RECT 84.750 82.700 84.950 83.100 ;
        RECT 86.550 82.700 86.750 83.100 ;
        RECT 83.850 82.400 84.450 82.700 ;
        RECT 84.750 82.500 86.750 82.700 ;
        RECT 75.850 81.100 76.050 81.800 ;
        RECT 77.850 81.700 78.450 82.300 ;
        RECT 78.750 81.300 79.350 81.900 ;
        RECT 79.550 81.800 80.150 82.400 ;
        RECT 84.050 82.300 84.450 82.400 ;
        RECT 86.550 82.400 86.750 82.500 ;
        RECT 87.550 82.700 87.750 83.100 ;
        RECT 88.450 82.700 88.650 83.100 ;
        RECT 90.250 82.700 90.450 83.100 ;
        RECT 87.550 82.400 88.150 82.700 ;
        RECT 88.450 82.500 90.450 82.700 ;
        RECT 84.950 81.800 85.350 82.200 ;
        RECT 79.550 81.100 79.750 81.800 ;
        RECT 85.750 81.300 86.350 81.900 ;
        RECT 86.550 81.800 87.150 82.400 ;
        RECT 87.750 82.300 88.150 82.400 ;
        RECT 90.250 82.400 90.450 82.500 ;
        RECT 94.550 82.700 94.750 83.100 ;
        RECT 95.450 82.700 95.650 83.100 ;
        RECT 97.250 82.700 97.450 83.100 ;
        RECT 94.550 82.400 95.150 82.700 ;
        RECT 95.450 82.500 97.450 82.700 ;
        RECT 86.550 81.100 86.750 81.800 ;
        RECT 88.550 81.700 89.150 82.300 ;
        RECT 89.450 81.300 90.050 81.900 ;
        RECT 90.250 81.800 90.850 82.400 ;
        RECT 94.750 82.300 95.150 82.400 ;
        RECT 97.250 82.400 97.450 82.500 ;
        RECT 98.250 82.700 98.450 83.100 ;
        RECT 99.150 82.700 99.350 83.100 ;
        RECT 100.950 82.700 101.150 83.100 ;
        RECT 98.250 82.400 98.850 82.700 ;
        RECT 99.150 82.500 101.150 82.700 ;
        RECT 95.650 81.800 96.050 82.200 ;
        RECT 90.250 81.100 90.450 81.800 ;
        RECT 96.450 81.300 97.050 81.900 ;
        RECT 97.250 81.800 97.850 82.400 ;
        RECT 98.450 82.300 98.850 82.400 ;
        RECT 100.950 82.400 101.150 82.500 ;
        RECT 97.250 81.100 97.450 81.800 ;
        RECT 99.250 81.700 99.850 82.300 ;
        RECT 100.150 81.300 100.750 81.900 ;
        RECT 100.950 81.800 101.550 82.400 ;
        RECT 100.950 81.100 101.150 81.800 ;
        RECT 21.650 80.300 22.050 81.100 ;
        RECT 22.550 80.300 22.950 81.100 ;
        RECT 23.450 80.300 23.850 81.100 ;
        RECT 24.350 80.300 24.750 81.100 ;
        RECT 25.350 80.300 25.750 81.100 ;
        RECT 26.250 80.300 26.650 81.100 ;
        RECT 27.150 80.300 27.550 81.100 ;
        RECT 28.050 80.300 28.450 81.100 ;
        RECT 30.250 80.300 30.650 81.100 ;
        RECT 31.150 80.300 31.550 81.100 ;
        RECT 32.050 80.300 32.450 81.100 ;
        RECT 32.950 80.300 33.350 81.100 ;
        RECT 33.950 80.300 34.350 81.100 ;
        RECT 34.850 80.300 35.250 81.100 ;
        RECT 35.750 80.300 36.150 81.100 ;
        RECT 36.650 80.300 37.050 81.100 ;
        RECT 40.950 80.300 41.350 81.100 ;
        RECT 41.850 80.300 42.250 81.100 ;
        RECT 42.750 80.300 43.150 81.100 ;
        RECT 43.650 80.300 44.050 81.100 ;
        RECT 44.650 80.300 45.050 81.100 ;
        RECT 45.550 80.300 45.950 81.100 ;
        RECT 46.450 80.300 46.850 81.100 ;
        RECT 47.350 80.300 47.750 81.100 ;
        RECT 51.650 80.300 52.050 81.100 ;
        RECT 52.550 80.300 52.950 81.100 ;
        RECT 53.450 80.300 53.850 81.100 ;
        RECT 54.350 80.300 54.750 81.100 ;
        RECT 55.350 80.300 55.750 81.100 ;
        RECT 56.250 80.300 56.650 81.100 ;
        RECT 57.150 80.300 57.550 81.100 ;
        RECT 58.050 80.300 58.450 81.100 ;
        RECT 62.350 80.300 62.750 81.100 ;
        RECT 63.250 80.300 63.650 81.100 ;
        RECT 64.150 80.300 64.550 81.100 ;
        RECT 65.050 80.300 65.450 81.100 ;
        RECT 66.050 80.300 66.450 81.100 ;
        RECT 66.950 80.300 67.350 81.100 ;
        RECT 67.850 80.300 68.250 81.100 ;
        RECT 68.750 80.300 69.150 81.100 ;
        RECT 73.050 80.300 73.450 81.100 ;
        RECT 73.950 80.300 74.350 81.100 ;
        RECT 74.850 80.300 75.250 81.100 ;
        RECT 75.750 80.300 76.150 81.100 ;
        RECT 76.750 80.300 77.150 81.100 ;
        RECT 77.650 80.300 78.050 81.100 ;
        RECT 78.550 80.300 78.950 81.100 ;
        RECT 79.450 80.300 79.850 81.100 ;
        RECT 83.750 80.300 84.150 81.100 ;
        RECT 84.650 80.300 85.050 81.100 ;
        RECT 85.550 80.300 85.950 81.100 ;
        RECT 86.450 80.300 86.850 81.100 ;
        RECT 87.450 80.300 87.850 81.100 ;
        RECT 88.350 80.300 88.750 81.100 ;
        RECT 89.250 80.300 89.650 81.100 ;
        RECT 90.150 80.300 90.550 81.100 ;
        RECT 94.450 80.300 94.850 81.100 ;
        RECT 95.350 80.300 95.750 81.100 ;
        RECT 96.250 80.300 96.650 81.100 ;
        RECT 97.150 80.300 97.550 81.100 ;
        RECT 98.150 80.300 98.550 81.100 ;
        RECT 99.050 80.300 99.450 81.100 ;
        RECT 99.950 80.300 100.350 81.100 ;
        RECT 100.850 80.300 101.250 81.100 ;
        RECT 21.750 79.700 21.950 80.300 ;
        RECT 25.450 79.700 25.650 80.300 ;
        RECT 30.350 79.700 30.550 80.300 ;
        RECT 34.050 79.700 34.250 80.300 ;
        RECT 41.050 79.700 41.250 80.300 ;
        RECT 44.750 79.700 44.950 80.300 ;
        RECT 51.750 79.700 51.950 80.300 ;
        RECT 55.450 79.700 55.650 80.300 ;
        RECT 62.450 79.700 62.650 80.300 ;
        RECT 66.150 79.700 66.350 80.300 ;
        RECT 73.150 79.700 73.350 80.300 ;
        RECT 76.850 79.700 77.050 80.300 ;
        RECT 83.850 79.700 84.050 80.300 ;
        RECT 87.550 79.700 87.750 80.300 ;
        RECT 94.550 79.700 94.750 80.300 ;
        RECT 98.250 79.700 98.450 80.300 ;
        RECT 20.650 78.300 102.150 79.700 ;
        RECT 21.750 77.700 21.950 78.300 ;
        RECT 25.450 77.700 25.650 78.300 ;
        RECT 30.350 77.700 30.550 78.300 ;
        RECT 34.050 77.700 34.250 78.300 ;
        RECT 41.050 77.700 41.250 78.300 ;
        RECT 44.750 77.700 44.950 78.300 ;
        RECT 51.750 77.700 51.950 78.300 ;
        RECT 55.450 77.700 55.650 78.300 ;
        RECT 62.450 77.700 62.650 78.300 ;
        RECT 66.150 77.700 66.350 78.300 ;
        RECT 73.150 77.700 73.350 78.300 ;
        RECT 76.850 77.700 77.050 78.300 ;
        RECT 83.850 77.700 84.050 78.300 ;
        RECT 87.550 77.700 87.750 78.300 ;
        RECT 94.550 77.700 94.750 78.300 ;
        RECT 98.250 77.700 98.450 78.300 ;
        RECT 21.650 76.900 22.050 77.700 ;
        RECT 22.550 76.900 22.950 77.700 ;
        RECT 23.450 76.900 23.850 77.700 ;
        RECT 24.350 76.900 24.750 77.700 ;
        RECT 25.350 76.900 25.750 77.700 ;
        RECT 26.250 76.900 26.650 77.700 ;
        RECT 27.150 76.900 27.550 77.700 ;
        RECT 28.050 76.900 28.450 77.700 ;
        RECT 30.250 76.900 30.650 77.700 ;
        RECT 31.150 76.900 31.550 77.700 ;
        RECT 32.050 76.900 32.450 77.700 ;
        RECT 32.950 76.900 33.350 77.700 ;
        RECT 33.950 76.900 34.350 77.700 ;
        RECT 34.850 76.900 35.250 77.700 ;
        RECT 35.750 76.900 36.150 77.700 ;
        RECT 36.650 76.900 37.050 77.700 ;
        RECT 40.950 76.900 41.350 77.700 ;
        RECT 41.850 76.900 42.250 77.700 ;
        RECT 42.750 76.900 43.150 77.700 ;
        RECT 43.650 76.900 44.050 77.700 ;
        RECT 44.650 76.900 45.050 77.700 ;
        RECT 45.550 76.900 45.950 77.700 ;
        RECT 46.450 76.900 46.850 77.700 ;
        RECT 47.350 76.900 47.750 77.700 ;
        RECT 51.650 76.900 52.050 77.700 ;
        RECT 52.550 76.900 52.950 77.700 ;
        RECT 53.450 76.900 53.850 77.700 ;
        RECT 54.350 76.900 54.750 77.700 ;
        RECT 55.350 76.900 55.750 77.700 ;
        RECT 56.250 76.900 56.650 77.700 ;
        RECT 57.150 76.900 57.550 77.700 ;
        RECT 58.050 76.900 58.450 77.700 ;
        RECT 62.350 76.900 62.750 77.700 ;
        RECT 63.250 76.900 63.650 77.700 ;
        RECT 64.150 76.900 64.550 77.700 ;
        RECT 65.050 76.900 65.450 77.700 ;
        RECT 66.050 76.900 66.450 77.700 ;
        RECT 66.950 76.900 67.350 77.700 ;
        RECT 67.850 76.900 68.250 77.700 ;
        RECT 68.750 76.900 69.150 77.700 ;
        RECT 73.050 76.900 73.450 77.700 ;
        RECT 73.950 76.900 74.350 77.700 ;
        RECT 74.850 76.900 75.250 77.700 ;
        RECT 75.750 76.900 76.150 77.700 ;
        RECT 76.750 76.900 77.150 77.700 ;
        RECT 77.650 76.900 78.050 77.700 ;
        RECT 78.550 76.900 78.950 77.700 ;
        RECT 79.450 76.900 79.850 77.700 ;
        RECT 83.750 76.900 84.150 77.700 ;
        RECT 84.650 76.900 85.050 77.700 ;
        RECT 85.550 76.900 85.950 77.700 ;
        RECT 86.450 76.900 86.850 77.700 ;
        RECT 87.450 76.900 87.850 77.700 ;
        RECT 88.350 76.900 88.750 77.700 ;
        RECT 89.250 76.900 89.650 77.700 ;
        RECT 90.150 76.900 90.550 77.700 ;
        RECT 94.450 76.900 94.850 77.700 ;
        RECT 95.350 76.900 95.750 77.700 ;
        RECT 96.250 76.900 96.650 77.700 ;
        RECT 97.150 76.900 97.550 77.700 ;
        RECT 98.150 76.900 98.550 77.700 ;
        RECT 99.050 76.900 99.450 77.700 ;
        RECT 99.950 76.900 100.350 77.700 ;
        RECT 100.850 76.900 101.250 77.700 ;
        RECT 23.750 76.200 24.150 76.600 ;
        RECT 24.450 76.200 24.650 76.900 ;
        RECT 22.850 75.800 23.250 76.200 ;
        RECT 21.950 75.300 22.350 75.700 ;
        RECT 24.450 75.600 25.050 76.200 ;
        RECT 26.550 75.800 26.950 76.200 ;
        RECT 27.350 76.100 27.950 76.700 ;
        RECT 28.150 76.200 28.350 76.900 ;
        RECT 32.350 76.200 32.750 76.600 ;
        RECT 33.050 76.200 33.250 76.900 ;
        RECT 24.450 75.500 24.650 75.600 ;
        RECT 22.650 75.300 24.650 75.500 ;
        RECT 25.650 75.300 26.050 75.700 ;
        RECT 28.150 75.600 28.750 76.200 ;
        RECT 31.450 75.800 31.850 76.200 ;
        RECT 28.150 75.500 28.350 75.600 ;
        RECT 26.350 75.300 28.350 75.500 ;
        RECT 30.550 75.300 30.950 75.700 ;
        RECT 33.050 75.600 33.650 76.200 ;
        RECT 35.150 75.800 35.550 76.200 ;
        RECT 35.950 76.100 36.550 76.700 ;
        RECT 36.750 76.200 36.950 76.900 ;
        RECT 43.050 76.200 43.450 76.600 ;
        RECT 43.750 76.200 43.950 76.900 ;
        RECT 33.050 75.500 33.250 75.600 ;
        RECT 31.250 75.300 33.250 75.500 ;
        RECT 34.250 75.300 34.650 75.700 ;
        RECT 36.750 75.600 37.350 76.200 ;
        RECT 42.150 75.800 42.550 76.200 ;
        RECT 36.750 75.500 36.950 75.600 ;
        RECT 34.950 75.300 36.950 75.500 ;
        RECT 41.250 75.300 41.650 75.700 ;
        RECT 43.750 75.600 44.350 76.200 ;
        RECT 45.850 75.800 46.250 76.200 ;
        RECT 46.650 76.100 47.250 76.700 ;
        RECT 47.450 76.200 47.650 76.900 ;
        RECT 53.750 76.200 54.150 76.600 ;
        RECT 54.450 76.200 54.650 76.900 ;
        RECT 43.750 75.500 43.950 75.600 ;
        RECT 41.950 75.300 43.950 75.500 ;
        RECT 44.950 75.300 45.350 75.700 ;
        RECT 47.450 75.600 48.050 76.200 ;
        RECT 52.850 75.800 53.250 76.200 ;
        RECT 47.450 75.500 47.650 75.600 ;
        RECT 45.650 75.300 47.650 75.500 ;
        RECT 51.950 75.300 52.350 75.700 ;
        RECT 54.450 75.600 55.050 76.200 ;
        RECT 56.550 75.800 56.950 76.200 ;
        RECT 57.350 76.100 57.950 76.700 ;
        RECT 58.150 76.200 58.350 76.900 ;
        RECT 64.450 76.200 64.850 76.600 ;
        RECT 65.150 76.200 65.350 76.900 ;
        RECT 54.450 75.500 54.650 75.600 ;
        RECT 52.650 75.300 54.650 75.500 ;
        RECT 55.650 75.300 56.050 75.700 ;
        RECT 58.150 75.600 58.750 76.200 ;
        RECT 63.550 75.800 63.950 76.200 ;
        RECT 58.150 75.500 58.350 75.600 ;
        RECT 56.350 75.300 58.350 75.500 ;
        RECT 62.650 75.300 63.050 75.700 ;
        RECT 65.150 75.600 65.750 76.200 ;
        RECT 67.250 75.800 67.650 76.200 ;
        RECT 68.050 76.100 68.650 76.700 ;
        RECT 68.850 76.200 69.050 76.900 ;
        RECT 75.150 76.200 75.550 76.600 ;
        RECT 75.850 76.200 76.050 76.900 ;
        RECT 65.150 75.500 65.350 75.600 ;
        RECT 63.350 75.300 65.350 75.500 ;
        RECT 66.350 75.300 66.750 75.700 ;
        RECT 68.850 75.600 69.450 76.200 ;
        RECT 74.250 75.800 74.650 76.200 ;
        RECT 68.850 75.500 69.050 75.600 ;
        RECT 67.050 75.300 69.050 75.500 ;
        RECT 73.350 75.300 73.750 75.700 ;
        RECT 75.850 75.600 76.450 76.200 ;
        RECT 77.950 75.800 78.350 76.200 ;
        RECT 78.750 76.100 79.350 76.700 ;
        RECT 79.550 76.200 79.750 76.900 ;
        RECT 85.850 76.200 86.250 76.600 ;
        RECT 86.550 76.200 86.750 76.900 ;
        RECT 75.850 75.500 76.050 75.600 ;
        RECT 74.050 75.300 76.050 75.500 ;
        RECT 77.050 75.300 77.450 75.700 ;
        RECT 79.550 75.600 80.150 76.200 ;
        RECT 84.950 75.800 85.350 76.200 ;
        RECT 79.550 75.500 79.750 75.600 ;
        RECT 77.750 75.300 79.750 75.500 ;
        RECT 84.050 75.300 84.450 75.700 ;
        RECT 86.550 75.600 87.150 76.200 ;
        RECT 88.650 75.800 89.050 76.200 ;
        RECT 89.450 76.100 90.050 76.700 ;
        RECT 90.250 76.200 90.450 76.900 ;
        RECT 96.550 76.200 96.950 76.600 ;
        RECT 97.250 76.200 97.450 76.900 ;
        RECT 86.550 75.500 86.750 75.600 ;
        RECT 84.750 75.300 86.750 75.500 ;
        RECT 87.750 75.300 88.150 75.700 ;
        RECT 90.250 75.600 90.850 76.200 ;
        RECT 95.650 75.800 96.050 76.200 ;
        RECT 90.250 75.500 90.450 75.600 ;
        RECT 88.450 75.300 90.450 75.500 ;
        RECT 94.750 75.300 95.150 75.700 ;
        RECT 97.250 75.600 97.850 76.200 ;
        RECT 99.350 75.800 99.750 76.200 ;
        RECT 100.150 76.100 100.750 76.700 ;
        RECT 100.950 76.200 101.150 76.900 ;
        RECT 97.250 75.500 97.450 75.600 ;
        RECT 95.450 75.300 97.450 75.500 ;
        RECT 98.450 75.300 98.850 75.700 ;
        RECT 100.950 75.600 101.550 76.200 ;
        RECT 100.950 75.500 101.150 75.600 ;
        RECT 99.150 75.300 101.150 75.500 ;
        RECT 22.650 74.900 22.850 75.300 ;
        RECT 24.450 74.900 24.650 75.300 ;
        RECT 26.350 74.900 26.550 75.300 ;
        RECT 28.150 74.900 28.350 75.300 ;
        RECT 31.250 74.900 31.450 75.300 ;
        RECT 33.050 74.900 33.250 75.300 ;
        RECT 34.950 74.900 35.150 75.300 ;
        RECT 36.750 74.900 36.950 75.300 ;
        RECT 41.950 74.900 42.150 75.300 ;
        RECT 43.750 74.900 43.950 75.300 ;
        RECT 45.650 74.900 45.850 75.300 ;
        RECT 47.450 74.900 47.650 75.300 ;
        RECT 52.650 74.900 52.850 75.300 ;
        RECT 54.450 74.900 54.650 75.300 ;
        RECT 56.350 74.900 56.550 75.300 ;
        RECT 58.150 74.900 58.350 75.300 ;
        RECT 63.350 74.900 63.550 75.300 ;
        RECT 65.150 74.900 65.350 75.300 ;
        RECT 67.050 74.900 67.250 75.300 ;
        RECT 68.850 74.900 69.050 75.300 ;
        RECT 74.050 74.900 74.250 75.300 ;
        RECT 75.850 74.900 76.050 75.300 ;
        RECT 77.750 74.900 77.950 75.300 ;
        RECT 79.550 74.900 79.750 75.300 ;
        RECT 84.750 74.900 84.950 75.300 ;
        RECT 86.550 74.900 86.750 75.300 ;
        RECT 88.450 74.900 88.650 75.300 ;
        RECT 90.250 74.900 90.450 75.300 ;
        RECT 95.450 74.900 95.650 75.300 ;
        RECT 97.250 74.900 97.450 75.300 ;
        RECT 99.150 74.900 99.350 75.300 ;
        RECT 100.950 74.900 101.150 75.300 ;
        RECT 21.650 73.600 22.050 74.900 ;
        RECT 22.550 73.600 22.950 74.900 ;
        RECT 23.450 73.600 23.850 74.900 ;
        RECT 24.350 73.600 24.750 74.900 ;
        RECT 25.350 73.600 25.750 74.900 ;
        RECT 26.250 73.600 26.650 74.900 ;
        RECT 27.150 73.600 27.550 74.900 ;
        RECT 28.050 73.600 28.450 74.900 ;
        RECT 30.250 73.600 30.650 74.900 ;
        RECT 31.150 73.600 31.550 74.900 ;
        RECT 32.050 73.600 32.450 74.900 ;
        RECT 32.950 73.600 33.350 74.900 ;
        RECT 33.950 73.600 34.350 74.900 ;
        RECT 34.850 73.600 35.250 74.900 ;
        RECT 35.750 73.600 36.150 74.900 ;
        RECT 36.650 73.600 37.050 74.900 ;
        RECT 40.950 73.600 41.350 74.900 ;
        RECT 41.850 73.600 42.250 74.900 ;
        RECT 42.750 73.600 43.150 74.900 ;
        RECT 43.650 73.600 44.050 74.900 ;
        RECT 44.650 73.600 45.050 74.900 ;
        RECT 45.550 73.600 45.950 74.900 ;
        RECT 46.450 73.600 46.850 74.900 ;
        RECT 47.350 73.600 47.750 74.900 ;
        RECT 51.650 73.600 52.050 74.900 ;
        RECT 52.550 73.600 52.950 74.900 ;
        RECT 53.450 73.600 53.850 74.900 ;
        RECT 54.350 73.600 54.750 74.900 ;
        RECT 55.350 73.600 55.750 74.900 ;
        RECT 56.250 73.600 56.650 74.900 ;
        RECT 57.150 73.600 57.550 74.900 ;
        RECT 58.050 73.600 58.450 74.900 ;
        RECT 62.350 73.600 62.750 74.900 ;
        RECT 63.250 73.600 63.650 74.900 ;
        RECT 64.150 73.600 64.550 74.900 ;
        RECT 65.050 73.600 65.450 74.900 ;
        RECT 66.050 73.600 66.450 74.900 ;
        RECT 66.950 73.600 67.350 74.900 ;
        RECT 67.850 73.600 68.250 74.900 ;
        RECT 68.750 73.600 69.150 74.900 ;
        RECT 73.050 73.600 73.450 74.900 ;
        RECT 73.950 73.600 74.350 74.900 ;
        RECT 74.850 73.600 75.250 74.900 ;
        RECT 75.750 73.600 76.150 74.900 ;
        RECT 76.750 73.600 77.150 74.900 ;
        RECT 77.650 73.600 78.050 74.900 ;
        RECT 78.550 73.600 78.950 74.900 ;
        RECT 79.450 73.600 79.850 74.900 ;
        RECT 83.750 73.600 84.150 74.900 ;
        RECT 84.650 73.600 85.050 74.900 ;
        RECT 85.550 73.600 85.950 74.900 ;
        RECT 86.450 73.600 86.850 74.900 ;
        RECT 87.450 73.600 87.850 74.900 ;
        RECT 88.350 73.600 88.750 74.900 ;
        RECT 89.250 73.600 89.650 74.900 ;
        RECT 90.150 73.600 90.550 74.900 ;
        RECT 94.450 73.600 94.850 74.900 ;
        RECT 95.350 73.600 95.750 74.900 ;
        RECT 96.250 73.600 96.650 74.900 ;
        RECT 97.150 73.600 97.550 74.900 ;
        RECT 98.150 73.600 98.550 74.900 ;
        RECT 99.050 73.600 99.450 74.900 ;
        RECT 99.950 73.600 100.350 74.900 ;
        RECT 100.850 73.600 101.250 74.900 ;
        RECT 21.750 73.000 21.950 73.600 ;
        RECT 23.550 73.000 23.750 73.600 ;
        RECT 25.450 73.000 25.650 73.600 ;
        RECT 27.250 73.000 27.450 73.600 ;
        RECT 30.350 73.000 30.550 73.600 ;
        RECT 32.150 73.000 32.350 73.600 ;
        RECT 34.050 73.000 34.250 73.600 ;
        RECT 35.850 73.000 36.050 73.600 ;
        RECT 41.050 73.000 41.250 73.600 ;
        RECT 42.850 73.000 43.050 73.600 ;
        RECT 44.750 73.000 44.950 73.600 ;
        RECT 46.550 73.000 46.750 73.600 ;
        RECT 51.750 73.000 51.950 73.600 ;
        RECT 53.550 73.000 53.750 73.600 ;
        RECT 55.450 73.000 55.650 73.600 ;
        RECT 57.250 73.000 57.450 73.600 ;
        RECT 62.450 73.000 62.650 73.600 ;
        RECT 64.250 73.000 64.450 73.600 ;
        RECT 66.150 73.000 66.350 73.600 ;
        RECT 67.950 73.000 68.150 73.600 ;
        RECT 73.150 73.000 73.350 73.600 ;
        RECT 74.950 73.000 75.150 73.600 ;
        RECT 76.850 73.000 77.050 73.600 ;
        RECT 78.650 73.000 78.850 73.600 ;
        RECT 83.850 73.000 84.050 73.600 ;
        RECT 85.650 73.000 85.850 73.600 ;
        RECT 87.550 73.000 87.750 73.600 ;
        RECT 89.350 73.000 89.550 73.600 ;
        RECT 94.550 73.000 94.750 73.600 ;
        RECT 96.350 73.000 96.550 73.600 ;
        RECT 98.250 73.000 98.450 73.600 ;
        RECT 100.050 73.000 100.250 73.600 ;
        RECT 17.150 71.800 101.550 73.000 ;
        RECT 21.750 71.200 21.950 71.800 ;
        RECT 23.550 71.200 23.750 71.800 ;
        RECT 25.450 71.200 25.650 71.800 ;
        RECT 27.250 71.200 27.450 71.800 ;
        RECT 30.350 71.200 30.550 71.800 ;
        RECT 32.150 71.200 32.350 71.800 ;
        RECT 34.050 71.200 34.250 71.800 ;
        RECT 35.850 71.200 36.050 71.800 ;
        RECT 41.050 71.200 41.250 71.800 ;
        RECT 42.850 71.200 43.050 71.800 ;
        RECT 44.750 71.200 44.950 71.800 ;
        RECT 46.550 71.200 46.750 71.800 ;
        RECT 51.750 71.200 51.950 71.800 ;
        RECT 53.550 71.200 53.750 71.800 ;
        RECT 55.450 71.200 55.650 71.800 ;
        RECT 57.250 71.200 57.450 71.800 ;
        RECT 62.450 71.200 62.650 71.800 ;
        RECT 64.250 71.200 64.450 71.800 ;
        RECT 66.150 71.200 66.350 71.800 ;
        RECT 67.950 71.200 68.150 71.800 ;
        RECT 73.150 71.200 73.350 71.800 ;
        RECT 74.950 71.200 75.150 71.800 ;
        RECT 76.850 71.200 77.050 71.800 ;
        RECT 78.650 71.200 78.850 71.800 ;
        RECT 83.850 71.200 84.050 71.800 ;
        RECT 85.650 71.200 85.850 71.800 ;
        RECT 87.550 71.200 87.750 71.800 ;
        RECT 89.350 71.200 89.550 71.800 ;
        RECT 94.550 71.200 94.750 71.800 ;
        RECT 96.350 71.200 96.550 71.800 ;
        RECT 98.250 71.200 98.450 71.800 ;
        RECT 100.050 71.200 100.250 71.800 ;
        RECT 21.650 69.900 22.050 71.200 ;
        RECT 22.550 69.900 22.950 71.200 ;
        RECT 23.450 69.900 23.850 71.200 ;
        RECT 24.350 69.900 24.750 71.200 ;
        RECT 25.350 69.900 25.750 71.200 ;
        RECT 26.250 69.900 26.650 71.200 ;
        RECT 27.150 69.900 27.550 71.200 ;
        RECT 28.050 69.900 28.450 71.200 ;
        RECT 30.250 69.900 30.650 71.200 ;
        RECT 31.150 69.900 31.550 71.200 ;
        RECT 32.050 69.900 32.450 71.200 ;
        RECT 32.950 69.900 33.350 71.200 ;
        RECT 33.950 69.900 34.350 71.200 ;
        RECT 34.850 69.900 35.250 71.200 ;
        RECT 35.750 69.900 36.150 71.200 ;
        RECT 36.650 69.900 37.050 71.200 ;
        RECT 40.950 69.900 41.350 71.200 ;
        RECT 41.850 69.900 42.250 71.200 ;
        RECT 42.750 69.900 43.150 71.200 ;
        RECT 43.650 69.900 44.050 71.200 ;
        RECT 44.650 69.900 45.050 71.200 ;
        RECT 45.550 69.900 45.950 71.200 ;
        RECT 46.450 69.900 46.850 71.200 ;
        RECT 47.350 69.900 47.750 71.200 ;
        RECT 51.650 69.900 52.050 71.200 ;
        RECT 52.550 69.900 52.950 71.200 ;
        RECT 53.450 69.900 53.850 71.200 ;
        RECT 54.350 69.900 54.750 71.200 ;
        RECT 55.350 69.900 55.750 71.200 ;
        RECT 56.250 69.900 56.650 71.200 ;
        RECT 57.150 69.900 57.550 71.200 ;
        RECT 58.050 69.900 58.450 71.200 ;
        RECT 62.350 69.900 62.750 71.200 ;
        RECT 63.250 69.900 63.650 71.200 ;
        RECT 64.150 69.900 64.550 71.200 ;
        RECT 65.050 69.900 65.450 71.200 ;
        RECT 66.050 69.900 66.450 71.200 ;
        RECT 66.950 69.900 67.350 71.200 ;
        RECT 67.850 69.900 68.250 71.200 ;
        RECT 68.750 69.900 69.150 71.200 ;
        RECT 73.050 69.900 73.450 71.200 ;
        RECT 73.950 69.900 74.350 71.200 ;
        RECT 74.850 69.900 75.250 71.200 ;
        RECT 75.750 69.900 76.150 71.200 ;
        RECT 76.750 69.900 77.150 71.200 ;
        RECT 77.650 69.900 78.050 71.200 ;
        RECT 78.550 69.900 78.950 71.200 ;
        RECT 79.450 69.900 79.850 71.200 ;
        RECT 83.750 69.900 84.150 71.200 ;
        RECT 84.650 69.900 85.050 71.200 ;
        RECT 85.550 69.900 85.950 71.200 ;
        RECT 86.450 69.900 86.850 71.200 ;
        RECT 87.450 69.900 87.850 71.200 ;
        RECT 88.350 69.900 88.750 71.200 ;
        RECT 89.250 69.900 89.650 71.200 ;
        RECT 90.150 69.900 90.550 71.200 ;
        RECT 94.450 69.900 94.850 71.200 ;
        RECT 95.350 69.900 95.750 71.200 ;
        RECT 96.250 69.900 96.650 71.200 ;
        RECT 97.150 69.900 97.550 71.200 ;
        RECT 98.150 69.900 98.550 71.200 ;
        RECT 99.050 69.900 99.450 71.200 ;
        RECT 99.950 69.900 100.350 71.200 ;
        RECT 100.850 69.900 101.250 71.200 ;
        RECT 21.850 69.000 22.450 69.600 ;
        RECT 22.650 69.500 22.850 69.900 ;
        RECT 24.450 69.500 24.650 69.900 ;
        RECT 26.350 69.500 26.550 69.900 ;
        RECT 28.150 69.500 28.350 69.900 ;
        RECT 22.650 69.300 24.650 69.500 ;
        RECT 24.450 69.200 24.650 69.300 ;
        RECT 22.750 68.500 23.350 69.100 ;
        RECT 24.450 68.600 25.050 69.200 ;
        RECT 25.650 69.100 26.050 69.500 ;
        RECT 26.350 69.300 28.350 69.500 ;
        RECT 28.150 69.200 28.350 69.300 ;
        RECT 23.750 68.200 24.150 68.600 ;
        RECT 24.450 67.900 24.650 68.600 ;
        RECT 26.450 68.500 27.050 69.100 ;
        RECT 28.150 68.600 28.750 69.200 ;
        RECT 30.450 69.000 31.050 69.600 ;
        RECT 31.250 69.500 31.450 69.900 ;
        RECT 33.050 69.500 33.250 69.900 ;
        RECT 34.950 69.500 35.150 69.900 ;
        RECT 36.750 69.500 36.950 69.900 ;
        RECT 31.250 69.300 33.250 69.500 ;
        RECT 33.050 69.200 33.250 69.300 ;
        RECT 27.450 68.200 27.850 68.600 ;
        RECT 28.150 67.900 28.350 68.600 ;
        RECT 31.350 68.500 31.950 69.100 ;
        RECT 33.050 68.600 33.650 69.200 ;
        RECT 34.250 69.100 34.650 69.500 ;
        RECT 34.950 69.300 36.950 69.500 ;
        RECT 36.750 69.200 36.950 69.300 ;
        RECT 32.350 68.200 32.750 68.600 ;
        RECT 33.050 67.900 33.250 68.600 ;
        RECT 35.050 68.500 35.650 69.100 ;
        RECT 36.750 68.600 37.350 69.200 ;
        RECT 41.150 69.000 41.750 69.600 ;
        RECT 41.950 69.500 42.150 69.900 ;
        RECT 43.750 69.500 43.950 69.900 ;
        RECT 45.650 69.500 45.850 69.900 ;
        RECT 47.450 69.500 47.650 69.900 ;
        RECT 41.950 69.300 43.950 69.500 ;
        RECT 43.750 69.200 43.950 69.300 ;
        RECT 36.050 68.200 36.450 68.600 ;
        RECT 36.750 67.900 36.950 68.600 ;
        RECT 42.050 68.500 42.650 69.100 ;
        RECT 43.750 68.600 44.350 69.200 ;
        RECT 44.950 69.100 45.350 69.500 ;
        RECT 45.650 69.300 47.650 69.500 ;
        RECT 47.450 69.200 47.650 69.300 ;
        RECT 43.050 68.200 43.450 68.600 ;
        RECT 43.750 67.900 43.950 68.600 ;
        RECT 45.750 68.500 46.350 69.100 ;
        RECT 47.450 68.600 48.050 69.200 ;
        RECT 51.850 69.000 52.450 69.600 ;
        RECT 52.650 69.500 52.850 69.900 ;
        RECT 54.450 69.500 54.650 69.900 ;
        RECT 56.350 69.500 56.550 69.900 ;
        RECT 58.150 69.500 58.350 69.900 ;
        RECT 52.650 69.300 54.650 69.500 ;
        RECT 54.450 69.200 54.650 69.300 ;
        RECT 46.750 68.200 47.150 68.600 ;
        RECT 47.450 67.900 47.650 68.600 ;
        RECT 52.750 68.500 53.350 69.100 ;
        RECT 54.450 68.600 55.050 69.200 ;
        RECT 55.650 69.100 56.050 69.500 ;
        RECT 56.350 69.300 58.350 69.500 ;
        RECT 58.150 69.200 58.350 69.300 ;
        RECT 53.750 68.200 54.150 68.600 ;
        RECT 54.450 67.900 54.650 68.600 ;
        RECT 56.450 68.500 57.050 69.100 ;
        RECT 58.150 68.600 58.750 69.200 ;
        RECT 62.550 69.000 63.150 69.600 ;
        RECT 63.350 69.500 63.550 69.900 ;
        RECT 65.150 69.500 65.350 69.900 ;
        RECT 67.050 69.500 67.250 69.900 ;
        RECT 68.850 69.500 69.050 69.900 ;
        RECT 63.350 69.300 65.350 69.500 ;
        RECT 65.150 69.200 65.350 69.300 ;
        RECT 57.450 68.200 57.850 68.600 ;
        RECT 58.150 67.900 58.350 68.600 ;
        RECT 63.450 68.500 64.050 69.100 ;
        RECT 65.150 68.600 65.750 69.200 ;
        RECT 66.350 69.100 66.750 69.500 ;
        RECT 67.050 69.300 69.050 69.500 ;
        RECT 68.850 69.200 69.050 69.300 ;
        RECT 64.450 68.200 64.850 68.600 ;
        RECT 65.150 67.900 65.350 68.600 ;
        RECT 67.150 68.500 67.750 69.100 ;
        RECT 68.850 68.600 69.450 69.200 ;
        RECT 73.250 69.000 73.850 69.600 ;
        RECT 74.050 69.500 74.250 69.900 ;
        RECT 75.850 69.500 76.050 69.900 ;
        RECT 77.750 69.500 77.950 69.900 ;
        RECT 79.550 69.500 79.750 69.900 ;
        RECT 74.050 69.300 76.050 69.500 ;
        RECT 75.850 69.200 76.050 69.300 ;
        RECT 68.150 68.200 68.550 68.600 ;
        RECT 68.850 67.900 69.050 68.600 ;
        RECT 74.150 68.500 74.750 69.100 ;
        RECT 75.850 68.600 76.450 69.200 ;
        RECT 77.050 69.100 77.450 69.500 ;
        RECT 77.750 69.300 79.750 69.500 ;
        RECT 79.550 69.200 79.750 69.300 ;
        RECT 75.150 68.200 75.550 68.600 ;
        RECT 75.850 67.900 76.050 68.600 ;
        RECT 77.850 68.500 78.450 69.100 ;
        RECT 79.550 68.600 80.150 69.200 ;
        RECT 83.950 69.000 84.550 69.600 ;
        RECT 84.750 69.500 84.950 69.900 ;
        RECT 86.550 69.500 86.750 69.900 ;
        RECT 88.450 69.500 88.650 69.900 ;
        RECT 90.250 69.500 90.450 69.900 ;
        RECT 84.750 69.300 86.750 69.500 ;
        RECT 86.550 69.200 86.750 69.300 ;
        RECT 78.850 68.200 79.250 68.600 ;
        RECT 79.550 67.900 79.750 68.600 ;
        RECT 84.850 68.500 85.450 69.100 ;
        RECT 86.550 68.600 87.150 69.200 ;
        RECT 87.750 69.100 88.150 69.500 ;
        RECT 88.450 69.300 90.450 69.500 ;
        RECT 90.250 69.200 90.450 69.300 ;
        RECT 85.850 68.200 86.250 68.600 ;
        RECT 86.550 67.900 86.750 68.600 ;
        RECT 88.550 68.500 89.150 69.100 ;
        RECT 90.250 68.600 90.850 69.200 ;
        RECT 94.650 69.000 95.250 69.600 ;
        RECT 95.450 69.500 95.650 69.900 ;
        RECT 97.250 69.500 97.450 69.900 ;
        RECT 99.150 69.500 99.350 69.900 ;
        RECT 100.950 69.500 101.150 69.900 ;
        RECT 95.450 69.300 97.450 69.500 ;
        RECT 97.250 69.200 97.450 69.300 ;
        RECT 89.550 68.200 89.950 68.600 ;
        RECT 90.250 67.900 90.450 68.600 ;
        RECT 95.550 68.500 96.150 69.100 ;
        RECT 97.250 68.600 97.850 69.200 ;
        RECT 98.450 69.100 98.850 69.500 ;
        RECT 99.150 69.300 101.150 69.500 ;
        RECT 100.950 69.200 101.150 69.300 ;
        RECT 96.550 68.200 96.950 68.600 ;
        RECT 97.250 67.900 97.450 68.600 ;
        RECT 99.250 68.500 99.850 69.100 ;
        RECT 100.950 68.600 101.550 69.200 ;
        RECT 100.250 68.200 100.650 68.600 ;
        RECT 100.950 67.900 101.150 68.600 ;
        RECT 21.650 67.100 22.050 67.900 ;
        RECT 22.550 67.100 22.950 67.900 ;
        RECT 23.450 67.100 23.850 67.900 ;
        RECT 24.350 67.100 24.750 67.900 ;
        RECT 25.350 67.100 25.750 67.900 ;
        RECT 26.250 67.100 26.650 67.900 ;
        RECT 27.150 67.100 27.550 67.900 ;
        RECT 28.050 67.100 28.450 67.900 ;
        RECT 30.250 67.100 30.650 67.900 ;
        RECT 31.150 67.100 31.550 67.900 ;
        RECT 32.050 67.100 32.450 67.900 ;
        RECT 32.950 67.100 33.350 67.900 ;
        RECT 33.950 67.100 34.350 67.900 ;
        RECT 34.850 67.100 35.250 67.900 ;
        RECT 35.750 67.100 36.150 67.900 ;
        RECT 36.650 67.100 37.050 67.900 ;
        RECT 40.950 67.100 41.350 67.900 ;
        RECT 41.850 67.100 42.250 67.900 ;
        RECT 42.750 67.100 43.150 67.900 ;
        RECT 43.650 67.100 44.050 67.900 ;
        RECT 44.650 67.100 45.050 67.900 ;
        RECT 45.550 67.100 45.950 67.900 ;
        RECT 46.450 67.100 46.850 67.900 ;
        RECT 47.350 67.100 47.750 67.900 ;
        RECT 51.650 67.100 52.050 67.900 ;
        RECT 52.550 67.100 52.950 67.900 ;
        RECT 53.450 67.100 53.850 67.900 ;
        RECT 54.350 67.100 54.750 67.900 ;
        RECT 55.350 67.100 55.750 67.900 ;
        RECT 56.250 67.100 56.650 67.900 ;
        RECT 57.150 67.100 57.550 67.900 ;
        RECT 58.050 67.100 58.450 67.900 ;
        RECT 62.350 67.100 62.750 67.900 ;
        RECT 63.250 67.100 63.650 67.900 ;
        RECT 64.150 67.100 64.550 67.900 ;
        RECT 65.050 67.100 65.450 67.900 ;
        RECT 66.050 67.100 66.450 67.900 ;
        RECT 66.950 67.100 67.350 67.900 ;
        RECT 67.850 67.100 68.250 67.900 ;
        RECT 68.750 67.100 69.150 67.900 ;
        RECT 73.050 67.100 73.450 67.900 ;
        RECT 73.950 67.100 74.350 67.900 ;
        RECT 74.850 67.100 75.250 67.900 ;
        RECT 75.750 67.100 76.150 67.900 ;
        RECT 76.750 67.100 77.150 67.900 ;
        RECT 77.650 67.100 78.050 67.900 ;
        RECT 78.550 67.100 78.950 67.900 ;
        RECT 79.450 67.100 79.850 67.900 ;
        RECT 83.750 67.100 84.150 67.900 ;
        RECT 84.650 67.100 85.050 67.900 ;
        RECT 85.550 67.100 85.950 67.900 ;
        RECT 86.450 67.100 86.850 67.900 ;
        RECT 87.450 67.100 87.850 67.900 ;
        RECT 88.350 67.100 88.750 67.900 ;
        RECT 89.250 67.100 89.650 67.900 ;
        RECT 90.150 67.100 90.550 67.900 ;
        RECT 94.450 67.100 94.850 67.900 ;
        RECT 95.350 67.100 95.750 67.900 ;
        RECT 96.250 67.100 96.650 67.900 ;
        RECT 97.150 67.100 97.550 67.900 ;
        RECT 98.150 67.100 98.550 67.900 ;
        RECT 99.050 67.100 99.450 67.900 ;
        RECT 99.950 67.100 100.350 67.900 ;
        RECT 100.850 67.100 101.250 67.900 ;
        RECT 21.750 66.500 21.950 67.100 ;
        RECT 25.450 66.500 25.650 67.100 ;
        RECT 30.350 66.500 30.550 67.100 ;
        RECT 34.050 66.500 34.250 67.100 ;
        RECT 41.050 66.500 41.250 67.100 ;
        RECT 44.750 66.500 44.950 67.100 ;
        RECT 51.750 66.500 51.950 67.100 ;
        RECT 55.450 66.500 55.650 67.100 ;
        RECT 62.450 66.500 62.650 67.100 ;
        RECT 66.150 66.500 66.350 67.100 ;
        RECT 73.150 66.500 73.350 67.100 ;
        RECT 76.850 66.500 77.050 67.100 ;
        RECT 83.850 66.500 84.050 67.100 ;
        RECT 87.550 66.500 87.750 67.100 ;
        RECT 94.550 66.500 94.750 67.100 ;
        RECT 98.250 66.500 98.450 67.100 ;
        RECT 21.150 65.300 101.550 66.500 ;
      LAYER met1 ;
        RECT 32.650 98.200 34.950 99.400 ;
        RECT 41.050 98.200 43.350 99.400 ;
        RECT 52.750 98.200 55.050 99.400 ;
        RECT 62.150 98.200 64.450 99.400 ;
        RECT 73.950 98.200 76.250 99.400 ;
        RECT 84.450 98.200 86.750 99.400 ;
        RECT 36.250 96.400 36.650 96.500 ;
        RECT 28.550 96.200 36.650 96.400 ;
        RECT 28.550 95.300 28.750 96.200 ;
        RECT 36.250 96.100 36.650 96.200 ;
        RECT 39.450 96.400 39.950 96.600 ;
        RECT 46.950 96.400 47.350 96.500 ;
        RECT 39.450 96.200 47.350 96.400 ;
        RECT 39.450 96.100 39.950 96.200 ;
        RECT 37.050 95.600 37.450 96.000 ;
        RECT 28.550 94.700 29.150 95.300 ;
        RECT 23.850 91.200 24.250 91.300 ;
        RECT 21.350 91.000 24.250 91.200 ;
        RECT 28.550 91.100 28.750 94.700 ;
        RECT 32.450 91.200 32.850 91.300 ;
        RECT 21.350 90.800 21.550 91.000 ;
        RECT 23.850 90.900 24.250 91.000 ;
        RECT 28.450 91.000 28.850 91.100 ;
        RECT 29.950 91.000 32.850 91.200 ;
        RECT 37.150 91.100 37.350 95.600 ;
        RECT 37.750 93.400 40.150 94.500 ;
        RECT 40.650 91.200 40.850 96.200 ;
        RECT 46.950 96.100 47.350 96.200 ;
        RECT 50.150 96.400 50.650 96.600 ;
        RECT 57.650 96.400 58.050 96.500 ;
        RECT 50.150 96.200 58.050 96.400 ;
        RECT 50.150 96.100 50.650 96.200 ;
        RECT 47.750 95.600 48.150 96.000 ;
        RECT 43.150 91.200 43.550 91.300 ;
        RECT 28.450 90.800 30.150 91.000 ;
        RECT 32.450 90.900 32.850 91.000 ;
        RECT 37.050 91.000 37.450 91.100 ;
        RECT 37.850 91.000 38.450 91.200 ;
        RECT 37.050 90.800 38.450 91.000 ;
        RECT 40.650 91.000 43.550 91.200 ;
        RECT 47.850 91.100 48.050 95.600 ;
        RECT 48.450 93.400 50.850 94.500 ;
        RECT 51.350 91.200 51.550 96.200 ;
        RECT 57.650 96.100 58.050 96.200 ;
        RECT 60.850 96.400 61.350 96.600 ;
        RECT 68.350 96.400 68.750 96.500 ;
        RECT 60.850 96.200 68.750 96.400 ;
        RECT 60.850 96.100 61.350 96.200 ;
        RECT 58.450 95.600 58.850 96.000 ;
        RECT 53.850 91.200 54.250 91.300 ;
        RECT 40.650 90.800 40.850 91.000 ;
        RECT 43.150 90.900 43.550 91.000 ;
        RECT 47.750 91.000 48.150 91.100 ;
        RECT 48.550 91.000 49.150 91.200 ;
        RECT 47.750 90.800 49.150 91.000 ;
        RECT 51.350 91.000 54.250 91.200 ;
        RECT 58.550 91.100 58.750 95.600 ;
        RECT 59.150 93.400 61.550 94.500 ;
        RECT 62.050 91.200 62.250 96.200 ;
        RECT 68.350 96.100 68.750 96.200 ;
        RECT 71.550 96.400 72.050 96.600 ;
        RECT 79.050 96.400 79.450 96.500 ;
        RECT 71.550 96.200 79.450 96.400 ;
        RECT 71.550 96.100 72.050 96.200 ;
        RECT 69.150 95.600 69.550 96.000 ;
        RECT 64.550 91.200 64.950 91.300 ;
        RECT 51.350 90.800 51.550 91.000 ;
        RECT 53.850 90.900 54.250 91.000 ;
        RECT 58.450 91.000 58.850 91.100 ;
        RECT 59.250 91.000 59.850 91.200 ;
        RECT 58.450 90.800 59.850 91.000 ;
        RECT 62.050 91.000 64.950 91.200 ;
        RECT 69.250 91.100 69.450 95.600 ;
        RECT 69.850 93.400 72.250 94.500 ;
        RECT 72.750 91.200 72.950 96.200 ;
        RECT 79.050 96.100 79.450 96.200 ;
        RECT 82.250 96.400 82.750 96.600 ;
        RECT 89.750 96.400 90.150 96.500 ;
        RECT 82.250 96.200 90.150 96.400 ;
        RECT 82.250 96.100 82.750 96.200 ;
        RECT 79.850 95.600 80.250 96.000 ;
        RECT 75.250 91.200 75.650 91.300 ;
        RECT 62.050 90.800 62.250 91.000 ;
        RECT 64.550 90.900 64.950 91.000 ;
        RECT 69.150 91.000 69.550 91.100 ;
        RECT 69.950 91.000 70.550 91.200 ;
        RECT 69.150 90.800 70.550 91.000 ;
        RECT 72.750 91.000 75.650 91.200 ;
        RECT 79.950 91.100 80.150 95.600 ;
        RECT 80.550 93.400 82.950 94.500 ;
        RECT 83.450 91.200 83.650 96.200 ;
        RECT 89.750 96.100 90.150 96.200 ;
        RECT 92.950 96.400 93.450 96.600 ;
        RECT 92.950 96.200 94.350 96.400 ;
        RECT 92.950 96.100 93.450 96.200 ;
        RECT 90.550 95.600 90.950 96.000 ;
        RECT 85.950 91.200 86.350 91.300 ;
        RECT 72.750 90.800 72.950 91.000 ;
        RECT 75.250 90.900 75.650 91.000 ;
        RECT 79.850 91.000 80.250 91.100 ;
        RECT 80.650 91.000 81.250 91.200 ;
        RECT 79.850 90.800 81.250 91.000 ;
        RECT 83.450 91.000 86.350 91.200 ;
        RECT 90.650 91.100 90.850 95.600 ;
        RECT 91.250 93.400 93.650 94.500 ;
        RECT 94.150 91.200 94.350 96.200 ;
        RECT 96.650 91.200 97.050 91.300 ;
        RECT 83.450 90.800 83.650 91.000 ;
        RECT 85.950 90.900 86.350 91.000 ;
        RECT 90.550 91.000 90.950 91.100 ;
        RECT 91.350 91.000 91.950 91.200 ;
        RECT 90.550 90.800 91.950 91.000 ;
        RECT 94.150 91.000 97.050 91.200 ;
        RECT 94.150 90.800 94.350 91.000 ;
        RECT 96.650 90.900 97.050 91.000 ;
        RECT 101.250 91.000 101.650 91.100 ;
        RECT 102.050 91.000 102.650 91.200 ;
        RECT 101.250 90.800 102.650 91.000 ;
        RECT 21.250 90.400 21.650 90.800 ;
        RECT 28.450 90.700 28.850 90.800 ;
        RECT 24.850 89.900 25.450 90.500 ;
        RECT 20.950 85.200 22.150 86.000 ;
        RECT 28.650 82.400 28.850 90.700 ;
        RECT 29.850 90.400 30.250 90.800 ;
        RECT 37.050 90.700 37.450 90.800 ;
        RECT 33.450 89.900 34.050 90.500 ;
        RECT 37.250 82.400 37.450 90.700 ;
        RECT 37.850 90.600 38.450 90.800 ;
        RECT 40.550 90.400 40.950 90.800 ;
        RECT 47.750 90.700 48.150 90.800 ;
        RECT 44.150 89.900 44.750 90.500 ;
        RECT 38.050 85.000 40.350 86.200 ;
        RECT 47.950 82.400 48.150 90.700 ;
        RECT 48.550 90.600 49.150 90.800 ;
        RECT 51.250 90.400 51.650 90.800 ;
        RECT 58.450 90.700 58.850 90.800 ;
        RECT 54.850 89.900 55.450 90.500 ;
        RECT 48.750 85.000 51.050 86.200 ;
        RECT 58.650 82.400 58.850 90.700 ;
        RECT 59.250 90.600 59.850 90.800 ;
        RECT 61.950 90.400 62.350 90.800 ;
        RECT 69.150 90.700 69.550 90.800 ;
        RECT 65.550 89.900 66.150 90.500 ;
        RECT 59.450 85.000 61.750 86.200 ;
        RECT 69.350 82.400 69.550 90.700 ;
        RECT 69.950 90.600 70.550 90.800 ;
        RECT 72.650 90.400 73.050 90.800 ;
        RECT 79.850 90.700 80.250 90.800 ;
        RECT 76.250 89.900 76.850 90.500 ;
        RECT 70.150 85.000 72.450 86.200 ;
        RECT 80.050 82.400 80.250 90.700 ;
        RECT 80.650 90.600 81.250 90.800 ;
        RECT 83.350 90.400 83.750 90.800 ;
        RECT 90.550 90.700 90.950 90.800 ;
        RECT 86.950 89.900 87.550 90.500 ;
        RECT 80.850 85.000 83.150 86.200 ;
        RECT 90.750 82.400 90.950 90.700 ;
        RECT 91.350 90.600 91.950 90.800 ;
        RECT 94.050 90.400 94.450 90.800 ;
        RECT 101.250 90.700 101.650 90.800 ;
        RECT 97.650 89.900 98.250 90.500 ;
        RECT 91.550 85.000 93.850 86.200 ;
        RECT 101.450 82.400 101.650 90.700 ;
        RECT 102.050 90.600 102.650 90.800 ;
        RECT 22.850 81.900 23.250 82.200 ;
        RECT 21.150 81.800 23.250 81.900 ;
        RECT 21.150 81.700 23.150 81.800 ;
        RECT 17.150 71.800 19.800 73.000 ;
        RECT 21.150 68.200 21.350 81.700 ;
        RECT 23.650 81.300 24.250 81.900 ;
        RECT 24.450 81.800 25.050 82.400 ;
        RECT 24.650 80.700 24.850 81.800 ;
        RECT 26.450 81.700 27.050 82.300 ;
        RECT 27.350 81.300 27.950 81.900 ;
        RECT 28.150 81.800 28.850 82.400 ;
        RECT 31.450 81.900 31.850 82.200 ;
        RECT 29.750 81.800 31.850 81.900 ;
        RECT 22.050 80.500 24.850 80.700 ;
        RECT 22.050 75.700 22.250 80.500 ;
        RECT 28.450 80.300 28.650 81.800 ;
        RECT 25.750 80.100 28.650 80.300 ;
        RECT 29.750 81.700 31.750 81.800 ;
        RECT 25.050 76.700 25.550 76.900 ;
        RECT 23.850 76.600 25.550 76.700 ;
        RECT 23.750 76.500 25.550 76.600 ;
        RECT 23.750 76.200 24.150 76.500 ;
        RECT 25.050 76.400 25.550 76.500 ;
        RECT 22.850 75.800 23.250 76.200 ;
        RECT 21.950 75.300 22.350 75.700 ;
        RECT 21.850 69.000 22.450 69.600 ;
        RECT 22.950 69.100 23.150 75.800 ;
        RECT 24.450 75.600 25.050 76.200 ;
        RECT 25.750 75.700 25.950 80.100 ;
        RECT 26.550 75.800 26.950 76.200 ;
        RECT 27.350 76.100 27.950 76.700 ;
        RECT 25.650 75.300 26.050 75.700 ;
        RECT 26.550 73.300 26.750 75.800 ;
        RECT 25.750 73.100 26.750 73.300 ;
        RECT 25.750 69.500 25.950 73.100 ;
        RECT 27.550 71.400 27.750 76.100 ;
        RECT 28.150 75.600 28.750 76.200 ;
        RECT 27.550 71.200 29.350 71.400 ;
        RECT 25.650 69.200 26.050 69.500 ;
        RECT 24.450 69.100 26.050 69.200 ;
        RECT 22.750 68.500 23.350 69.100 ;
        RECT 24.450 69.000 25.850 69.100 ;
        RECT 24.450 68.600 25.050 69.000 ;
        RECT 23.750 68.200 24.150 68.600 ;
        RECT 26.450 68.500 27.050 69.100 ;
        RECT 27.550 68.600 27.750 71.200 ;
        RECT 28.150 68.600 28.750 69.200 ;
        RECT 27.450 68.200 27.850 68.600 ;
        RECT 21.150 68.000 24.050 68.200 ;
        RECT 23.850 67.500 24.050 68.000 ;
        RECT 28.450 67.500 28.650 68.600 ;
        RECT 23.850 67.300 28.650 67.500 ;
        RECT 29.150 64.100 29.350 71.200 ;
        RECT 29.750 68.200 29.950 81.700 ;
        RECT 32.250 81.300 32.850 81.900 ;
        RECT 33.050 81.800 33.650 82.400 ;
        RECT 33.250 80.700 33.450 81.800 ;
        RECT 35.050 81.700 35.650 82.300 ;
        RECT 35.950 81.300 36.550 81.900 ;
        RECT 36.750 81.800 37.450 82.400 ;
        RECT 42.150 81.900 42.550 82.200 ;
        RECT 40.450 81.800 42.550 81.900 ;
        RECT 30.650 80.500 33.450 80.700 ;
        RECT 30.650 75.700 30.850 80.500 ;
        RECT 37.050 80.300 37.250 81.800 ;
        RECT 34.350 80.100 37.250 80.300 ;
        RECT 40.450 81.700 42.450 81.800 ;
        RECT 33.650 76.700 34.150 76.900 ;
        RECT 32.450 76.600 34.150 76.700 ;
        RECT 32.350 76.500 34.150 76.600 ;
        RECT 32.350 76.200 32.750 76.500 ;
        RECT 33.650 76.400 34.150 76.500 ;
        RECT 31.450 75.800 31.850 76.200 ;
        RECT 30.550 75.300 30.950 75.700 ;
        RECT 30.450 69.000 31.050 69.600 ;
        RECT 31.550 69.100 31.750 75.800 ;
        RECT 33.050 75.600 33.650 76.200 ;
        RECT 34.350 75.700 34.550 80.100 ;
        RECT 37.650 78.500 40.050 79.600 ;
        RECT 35.150 75.800 35.550 76.200 ;
        RECT 35.950 76.100 36.550 76.700 ;
        RECT 34.250 75.300 34.650 75.700 ;
        RECT 35.150 73.300 35.350 75.800 ;
        RECT 34.350 73.100 35.350 73.300 ;
        RECT 34.350 69.500 34.550 73.100 ;
        RECT 36.150 71.400 36.350 76.100 ;
        RECT 36.750 75.600 37.350 76.200 ;
        RECT 37.450 71.800 39.750 73.000 ;
        RECT 36.150 71.200 37.750 71.400 ;
        RECT 34.250 69.200 34.650 69.500 ;
        RECT 33.050 69.100 34.650 69.200 ;
        RECT 31.350 68.500 31.950 69.100 ;
        RECT 33.050 69.000 34.450 69.100 ;
        RECT 33.050 68.600 33.650 69.000 ;
        RECT 32.350 68.200 32.750 68.600 ;
        RECT 35.050 68.500 35.650 69.100 ;
        RECT 36.150 68.600 36.350 71.200 ;
        RECT 36.750 68.600 37.350 69.200 ;
        RECT 36.050 68.200 36.450 68.600 ;
        RECT 29.750 68.000 32.650 68.200 ;
        RECT 32.450 67.500 32.650 68.000 ;
        RECT 37.050 67.500 37.250 68.600 ;
        RECT 32.450 67.300 37.250 67.500 ;
        RECT 29.750 65.300 32.150 66.400 ;
        RECT 37.550 64.300 37.750 71.200 ;
        RECT 40.450 68.200 40.650 81.700 ;
        RECT 42.950 81.300 43.550 81.900 ;
        RECT 43.750 81.800 44.350 82.400 ;
        RECT 43.950 80.700 44.150 81.800 ;
        RECT 45.750 81.700 46.350 82.300 ;
        RECT 46.650 81.300 47.250 81.900 ;
        RECT 47.450 81.800 48.150 82.400 ;
        RECT 52.850 81.900 53.250 82.200 ;
        RECT 51.150 81.800 53.250 81.900 ;
        RECT 41.350 80.500 44.150 80.700 ;
        RECT 41.350 75.700 41.550 80.500 ;
        RECT 47.750 80.300 47.950 81.800 ;
        RECT 45.050 80.100 47.950 80.300 ;
        RECT 51.150 81.700 53.150 81.800 ;
        RECT 44.350 76.700 44.850 76.900 ;
        RECT 43.150 76.600 44.850 76.700 ;
        RECT 43.050 76.500 44.850 76.600 ;
        RECT 43.050 76.200 43.450 76.500 ;
        RECT 44.350 76.400 44.850 76.500 ;
        RECT 42.150 75.800 42.550 76.200 ;
        RECT 41.250 75.300 41.650 75.700 ;
        RECT 41.150 69.000 41.750 69.600 ;
        RECT 42.250 69.100 42.450 75.800 ;
        RECT 43.750 75.600 44.350 76.200 ;
        RECT 45.050 75.700 45.250 80.100 ;
        RECT 48.350 78.500 50.750 79.600 ;
        RECT 45.850 75.800 46.250 76.200 ;
        RECT 46.650 76.100 47.250 76.700 ;
        RECT 44.950 75.300 45.350 75.700 ;
        RECT 45.850 73.300 46.050 75.800 ;
        RECT 45.050 73.100 46.050 73.300 ;
        RECT 45.050 69.500 45.250 73.100 ;
        RECT 46.850 71.400 47.050 76.100 ;
        RECT 47.450 75.600 48.050 76.200 ;
        RECT 48.050 71.800 50.350 73.000 ;
        RECT 46.850 71.200 48.450 71.400 ;
        RECT 44.950 69.200 45.350 69.500 ;
        RECT 43.750 69.100 45.350 69.200 ;
        RECT 42.050 68.500 42.650 69.100 ;
        RECT 43.750 69.000 45.150 69.100 ;
        RECT 43.750 68.600 44.350 69.000 ;
        RECT 43.050 68.200 43.450 68.600 ;
        RECT 45.750 68.500 46.350 69.100 ;
        RECT 46.850 68.600 47.050 71.200 ;
        RECT 47.450 68.600 48.050 69.200 ;
        RECT 46.750 68.200 47.150 68.600 ;
        RECT 40.450 68.000 43.350 68.200 ;
        RECT 43.150 67.500 43.350 68.000 ;
        RECT 47.750 67.500 47.950 68.600 ;
        RECT 43.150 67.300 47.950 67.500 ;
        RECT 38.550 65.300 40.950 66.400 ;
        RECT 36.950 64.100 37.750 64.300 ;
        RECT 48.250 64.100 48.450 71.200 ;
        RECT 51.150 68.200 51.350 81.700 ;
        RECT 53.650 81.300 54.250 81.900 ;
        RECT 54.450 81.800 55.050 82.400 ;
        RECT 54.650 80.700 54.850 81.800 ;
        RECT 56.450 81.700 57.050 82.300 ;
        RECT 57.350 81.300 57.950 81.900 ;
        RECT 58.150 81.800 58.850 82.400 ;
        RECT 63.550 81.900 63.950 82.200 ;
        RECT 61.850 81.800 63.950 81.900 ;
        RECT 52.050 80.500 54.850 80.700 ;
        RECT 52.050 75.700 52.250 80.500 ;
        RECT 58.450 80.300 58.650 81.800 ;
        RECT 55.750 80.100 58.650 80.300 ;
        RECT 61.850 81.700 63.850 81.800 ;
        RECT 55.050 76.700 55.550 76.900 ;
        RECT 53.850 76.600 55.550 76.700 ;
        RECT 53.750 76.500 55.550 76.600 ;
        RECT 53.750 76.200 54.150 76.500 ;
        RECT 55.050 76.400 55.550 76.500 ;
        RECT 52.850 75.800 53.250 76.200 ;
        RECT 51.950 75.300 52.350 75.700 ;
        RECT 51.850 69.000 52.450 69.600 ;
        RECT 52.950 69.100 53.150 75.800 ;
        RECT 54.450 75.600 55.050 76.200 ;
        RECT 55.750 75.700 55.950 80.100 ;
        RECT 59.050 78.500 61.450 79.600 ;
        RECT 56.550 75.800 56.950 76.200 ;
        RECT 57.350 76.100 57.950 76.700 ;
        RECT 55.650 75.300 56.050 75.700 ;
        RECT 56.550 73.300 56.750 75.800 ;
        RECT 55.750 73.100 56.750 73.300 ;
        RECT 55.750 69.500 55.950 73.100 ;
        RECT 57.550 71.400 57.750 76.100 ;
        RECT 58.150 75.600 58.750 76.200 ;
        RECT 58.950 71.800 61.250 73.000 ;
        RECT 57.550 71.200 59.150 71.400 ;
        RECT 55.650 69.200 56.050 69.500 ;
        RECT 54.450 69.100 56.050 69.200 ;
        RECT 52.750 68.500 53.350 69.100 ;
        RECT 54.450 69.000 55.850 69.100 ;
        RECT 54.450 68.600 55.050 69.000 ;
        RECT 53.750 68.200 54.150 68.600 ;
        RECT 56.450 68.500 57.050 69.100 ;
        RECT 57.550 68.600 57.750 71.200 ;
        RECT 58.150 68.600 58.750 69.200 ;
        RECT 57.450 68.200 57.850 68.600 ;
        RECT 51.150 68.000 54.050 68.200 ;
        RECT 53.850 67.500 54.050 68.000 ;
        RECT 58.450 67.500 58.650 68.600 ;
        RECT 53.850 67.300 58.650 67.500 ;
        RECT 49.150 65.300 51.550 66.400 ;
        RECT 58.950 64.100 59.150 71.200 ;
        RECT 61.850 68.200 62.050 81.700 ;
        RECT 64.350 81.300 64.950 81.900 ;
        RECT 65.150 81.800 65.750 82.400 ;
        RECT 65.350 80.700 65.550 81.800 ;
        RECT 67.150 81.700 67.750 82.300 ;
        RECT 68.050 81.300 68.650 81.900 ;
        RECT 68.850 81.800 69.550 82.400 ;
        RECT 74.250 81.900 74.650 82.200 ;
        RECT 72.550 81.800 74.650 81.900 ;
        RECT 62.750 80.500 65.550 80.700 ;
        RECT 62.750 75.700 62.950 80.500 ;
        RECT 69.150 80.300 69.350 81.800 ;
        RECT 66.450 80.100 69.350 80.300 ;
        RECT 72.550 81.700 74.550 81.800 ;
        RECT 65.750 76.700 66.250 76.900 ;
        RECT 64.550 76.600 66.250 76.700 ;
        RECT 64.450 76.500 66.250 76.600 ;
        RECT 64.450 76.200 64.850 76.500 ;
        RECT 65.750 76.400 66.250 76.500 ;
        RECT 63.550 75.800 63.950 76.200 ;
        RECT 62.650 75.300 63.050 75.700 ;
        RECT 62.550 69.000 63.150 69.600 ;
        RECT 63.650 69.100 63.850 75.800 ;
        RECT 65.150 75.600 65.750 76.200 ;
        RECT 66.450 75.700 66.650 80.100 ;
        RECT 69.750 78.500 72.150 79.600 ;
        RECT 67.250 75.800 67.650 76.200 ;
        RECT 68.050 76.100 68.650 76.700 ;
        RECT 66.350 75.300 66.750 75.700 ;
        RECT 67.250 73.300 67.450 75.800 ;
        RECT 66.450 73.100 67.450 73.300 ;
        RECT 66.450 69.500 66.650 73.100 ;
        RECT 68.250 71.400 68.450 76.100 ;
        RECT 68.850 75.600 69.450 76.200 ;
        RECT 69.350 71.800 71.650 73.000 ;
        RECT 68.250 71.200 69.850 71.400 ;
        RECT 66.350 69.200 66.750 69.500 ;
        RECT 65.150 69.100 66.750 69.200 ;
        RECT 63.450 68.500 64.050 69.100 ;
        RECT 65.150 69.000 66.550 69.100 ;
        RECT 65.150 68.600 65.750 69.000 ;
        RECT 64.450 68.200 64.850 68.600 ;
        RECT 67.150 68.500 67.750 69.100 ;
        RECT 68.250 68.600 68.450 71.200 ;
        RECT 68.850 68.600 69.450 69.200 ;
        RECT 68.150 68.200 68.550 68.600 ;
        RECT 61.850 68.000 64.750 68.200 ;
        RECT 64.550 67.500 64.750 68.000 ;
        RECT 69.150 67.500 69.350 68.600 ;
        RECT 64.550 67.300 69.350 67.500 ;
        RECT 59.850 65.300 62.250 66.400 ;
        RECT 69.650 64.100 69.850 71.200 ;
        RECT 72.550 68.200 72.750 81.700 ;
        RECT 75.050 81.300 75.650 81.900 ;
        RECT 75.850 81.800 76.450 82.400 ;
        RECT 76.050 80.700 76.250 81.800 ;
        RECT 77.850 81.700 78.450 82.300 ;
        RECT 78.750 81.300 79.350 81.900 ;
        RECT 79.550 81.800 80.250 82.400 ;
        RECT 84.950 81.900 85.350 82.200 ;
        RECT 83.250 81.800 85.350 81.900 ;
        RECT 73.450 80.500 76.250 80.700 ;
        RECT 73.450 75.700 73.650 80.500 ;
        RECT 79.850 80.300 80.050 81.800 ;
        RECT 77.150 80.100 80.050 80.300 ;
        RECT 83.250 81.700 85.250 81.800 ;
        RECT 76.450 76.700 76.950 76.900 ;
        RECT 75.250 76.600 76.950 76.700 ;
        RECT 75.150 76.500 76.950 76.600 ;
        RECT 75.150 76.200 75.550 76.500 ;
        RECT 76.450 76.400 76.950 76.500 ;
        RECT 74.250 75.800 74.650 76.200 ;
        RECT 73.350 75.300 73.750 75.700 ;
        RECT 73.250 69.000 73.850 69.600 ;
        RECT 74.350 69.100 74.550 75.800 ;
        RECT 75.850 75.600 76.450 76.200 ;
        RECT 77.150 75.700 77.350 80.100 ;
        RECT 80.450 78.500 82.850 79.600 ;
        RECT 77.950 75.800 78.350 76.200 ;
        RECT 78.750 76.100 79.350 76.700 ;
        RECT 77.050 75.300 77.450 75.700 ;
        RECT 77.950 73.300 78.150 75.800 ;
        RECT 77.150 73.100 78.150 73.300 ;
        RECT 77.150 69.500 77.350 73.100 ;
        RECT 78.950 71.400 79.150 76.100 ;
        RECT 79.550 75.600 80.150 76.200 ;
        RECT 79.950 71.800 82.250 73.000 ;
        RECT 78.950 71.200 80.550 71.400 ;
        RECT 77.050 69.200 77.450 69.500 ;
        RECT 75.850 69.100 77.450 69.200 ;
        RECT 74.150 68.500 74.750 69.100 ;
        RECT 75.850 69.000 77.250 69.100 ;
        RECT 75.850 68.600 76.450 69.000 ;
        RECT 75.150 68.200 75.550 68.600 ;
        RECT 77.850 68.500 78.450 69.100 ;
        RECT 78.950 68.600 79.150 71.200 ;
        RECT 79.550 68.600 80.150 69.200 ;
        RECT 78.850 68.200 79.250 68.600 ;
        RECT 72.550 68.000 75.450 68.200 ;
        RECT 75.250 67.500 75.450 68.000 ;
        RECT 79.850 67.500 80.050 68.600 ;
        RECT 75.250 67.300 80.050 67.500 ;
        RECT 71.050 65.300 73.450 66.400 ;
        RECT 80.350 64.100 80.550 71.200 ;
        RECT 83.250 68.200 83.450 81.700 ;
        RECT 85.750 81.300 86.350 81.900 ;
        RECT 86.550 81.800 87.150 82.400 ;
        RECT 86.750 80.700 86.950 81.800 ;
        RECT 88.550 81.700 89.150 82.300 ;
        RECT 89.450 81.300 90.050 81.900 ;
        RECT 90.250 81.800 90.950 82.400 ;
        RECT 95.650 81.900 96.050 82.200 ;
        RECT 93.950 81.800 96.050 81.900 ;
        RECT 84.150 80.500 86.950 80.700 ;
        RECT 84.150 75.700 84.350 80.500 ;
        RECT 90.550 80.300 90.750 81.800 ;
        RECT 87.850 80.100 90.750 80.300 ;
        RECT 93.950 81.700 95.950 81.800 ;
        RECT 87.150 76.700 87.650 76.900 ;
        RECT 85.950 76.600 87.650 76.700 ;
        RECT 85.850 76.500 87.650 76.600 ;
        RECT 85.850 76.200 86.250 76.500 ;
        RECT 87.150 76.400 87.650 76.500 ;
        RECT 84.950 75.800 85.350 76.200 ;
        RECT 84.050 75.300 84.450 75.700 ;
        RECT 83.950 69.000 84.550 69.600 ;
        RECT 85.050 69.100 85.250 75.800 ;
        RECT 86.550 75.600 87.150 76.200 ;
        RECT 87.850 75.700 88.050 80.100 ;
        RECT 91.150 78.500 93.550 79.600 ;
        RECT 88.650 75.800 89.050 76.200 ;
        RECT 89.450 76.100 90.050 76.700 ;
        RECT 87.750 75.300 88.150 75.700 ;
        RECT 88.650 73.300 88.850 75.800 ;
        RECT 87.850 73.100 88.850 73.300 ;
        RECT 87.850 69.500 88.050 73.100 ;
        RECT 89.650 71.400 89.850 76.100 ;
        RECT 90.250 75.600 90.850 76.200 ;
        RECT 90.750 71.800 93.050 73.000 ;
        RECT 89.650 71.200 91.450 71.400 ;
        RECT 87.750 69.200 88.150 69.500 ;
        RECT 86.550 69.100 88.150 69.200 ;
        RECT 84.850 68.500 85.450 69.100 ;
        RECT 86.550 69.000 87.950 69.100 ;
        RECT 86.550 68.600 87.150 69.000 ;
        RECT 85.850 68.200 86.250 68.600 ;
        RECT 88.550 68.500 89.150 69.100 ;
        RECT 89.650 68.600 89.850 71.200 ;
        RECT 90.250 68.600 90.850 69.200 ;
        RECT 89.550 68.200 89.950 68.600 ;
        RECT 83.250 68.000 86.150 68.200 ;
        RECT 85.950 67.500 86.150 68.000 ;
        RECT 90.550 67.500 90.750 68.600 ;
        RECT 85.950 67.300 90.750 67.500 ;
        RECT 81.550 65.300 83.950 66.400 ;
        RECT 91.250 64.100 91.450 71.200 ;
        RECT 93.950 68.200 94.150 81.700 ;
        RECT 96.450 81.300 97.050 81.900 ;
        RECT 97.250 81.800 97.850 82.400 ;
        RECT 97.450 80.700 97.650 81.800 ;
        RECT 99.250 81.700 99.850 82.300 ;
        RECT 100.150 81.300 100.750 81.900 ;
        RECT 100.950 81.800 101.650 82.400 ;
        RECT 94.850 80.500 97.650 80.700 ;
        RECT 94.850 75.700 95.050 80.500 ;
        RECT 101.250 80.300 101.450 81.800 ;
        RECT 98.550 80.100 101.450 80.300 ;
        RECT 97.850 76.700 98.350 76.900 ;
        RECT 96.650 76.600 98.350 76.700 ;
        RECT 96.550 76.500 98.350 76.600 ;
        RECT 96.550 76.200 96.950 76.500 ;
        RECT 97.850 76.400 98.350 76.500 ;
        RECT 95.650 75.800 96.050 76.200 ;
        RECT 94.750 75.300 95.150 75.700 ;
        RECT 94.650 69.000 95.250 69.600 ;
        RECT 95.750 69.100 95.950 75.800 ;
        RECT 97.250 75.600 97.850 76.200 ;
        RECT 98.550 75.700 98.750 80.100 ;
        RECT 99.350 75.800 99.750 76.200 ;
        RECT 100.150 76.100 100.750 76.700 ;
        RECT 98.450 75.300 98.850 75.700 ;
        RECT 99.350 73.300 99.550 75.800 ;
        RECT 98.550 73.100 99.550 73.300 ;
        RECT 98.550 69.500 98.750 73.100 ;
        RECT 100.350 71.400 100.550 76.100 ;
        RECT 100.950 75.600 101.550 76.200 ;
        RECT 100.350 71.200 102.050 71.400 ;
        RECT 98.450 69.200 98.850 69.500 ;
        RECT 97.250 69.100 98.850 69.200 ;
        RECT 95.550 68.500 96.150 69.100 ;
        RECT 97.250 69.000 98.650 69.100 ;
        RECT 97.250 68.600 97.850 69.000 ;
        RECT 96.550 68.200 96.950 68.600 ;
        RECT 99.250 68.500 99.850 69.100 ;
        RECT 100.350 68.600 100.550 71.200 ;
        RECT 100.950 68.600 101.550 69.200 ;
        RECT 100.250 68.200 100.650 68.600 ;
        RECT 93.950 68.000 96.850 68.200 ;
        RECT 96.650 67.500 96.850 68.000 ;
        RECT 101.250 67.500 101.450 68.600 ;
        RECT 96.650 67.300 101.450 67.500 ;
        RECT 92.350 65.300 94.750 66.400 ;
        RECT 101.850 64.100 102.050 71.200 ;
        RECT 29.150 63.900 102.050 64.100 ;
        RECT 36.950 63.700 37.550 63.900 ;
      LAYER met2 ;
        RECT 32.650 98.200 34.950 99.400 ;
        RECT 41.050 98.200 43.350 99.400 ;
        RECT 52.750 98.200 55.050 99.400 ;
        RECT 62.150 98.200 64.450 99.400 ;
        RECT 73.950 98.200 76.250 99.400 ;
        RECT 84.450 98.200 86.750 99.400 ;
        RECT 37.750 93.400 40.150 94.500 ;
        RECT 48.450 93.400 50.850 94.500 ;
        RECT 59.150 93.400 61.550 94.500 ;
        RECT 69.850 93.400 72.250 94.500 ;
        RECT 80.550 93.400 82.950 94.500 ;
        RECT 91.250 93.400 93.650 94.500 ;
        RECT 24.850 89.900 25.450 90.500 ;
        RECT 33.450 89.900 34.050 90.500 ;
        RECT 44.150 89.900 44.750 90.500 ;
        RECT 54.850 89.900 55.450 90.500 ;
        RECT 65.550 89.900 66.150 90.500 ;
        RECT 76.250 89.900 76.850 90.500 ;
        RECT 86.950 89.900 87.550 90.500 ;
        RECT 97.650 89.900 98.250 90.500 ;
        RECT 20.950 85.200 22.150 86.000 ;
        RECT 38.050 85.000 40.350 86.200 ;
        RECT 48.750 85.000 51.050 86.200 ;
        RECT 59.450 85.000 61.750 86.200 ;
        RECT 70.150 85.000 72.450 86.200 ;
        RECT 80.850 85.000 83.150 86.200 ;
        RECT 91.550 85.000 93.850 86.200 ;
        RECT 23.650 81.700 24.250 81.900 ;
        RECT 26.450 81.700 27.050 82.300 ;
        RECT 23.650 81.500 26.750 81.700 ;
        RECT 23.650 81.300 24.250 81.500 ;
        RECT 27.350 81.300 27.950 81.900 ;
        RECT 32.250 81.700 32.850 81.900 ;
        RECT 35.050 81.700 35.650 82.300 ;
        RECT 32.250 81.500 35.350 81.700 ;
        RECT 32.250 81.300 32.850 81.500 ;
        RECT 35.950 81.300 36.550 81.900 ;
        RECT 42.950 81.700 43.550 81.900 ;
        RECT 45.750 81.700 46.350 82.300 ;
        RECT 42.950 81.500 46.050 81.700 ;
        RECT 42.950 81.300 43.550 81.500 ;
        RECT 46.650 81.300 47.250 81.900 ;
        RECT 53.650 81.700 54.250 81.900 ;
        RECT 56.450 81.700 57.050 82.300 ;
        RECT 53.650 81.500 56.750 81.700 ;
        RECT 53.650 81.300 54.250 81.500 ;
        RECT 57.350 81.300 57.950 81.900 ;
        RECT 64.350 81.700 64.950 81.900 ;
        RECT 67.150 81.700 67.750 82.300 ;
        RECT 64.350 81.500 67.450 81.700 ;
        RECT 64.350 81.300 64.950 81.500 ;
        RECT 68.050 81.300 68.650 81.900 ;
        RECT 75.050 81.700 75.650 81.900 ;
        RECT 77.850 81.700 78.450 82.300 ;
        RECT 75.050 81.500 78.150 81.700 ;
        RECT 75.050 81.300 75.650 81.500 ;
        RECT 78.750 81.300 79.350 81.900 ;
        RECT 85.750 81.700 86.350 81.900 ;
        RECT 88.550 81.700 89.150 82.300 ;
        RECT 85.750 81.500 88.850 81.700 ;
        RECT 85.750 81.300 86.350 81.500 ;
        RECT 89.450 81.300 90.050 81.900 ;
        RECT 96.450 81.700 97.050 81.900 ;
        RECT 99.250 81.700 99.850 82.300 ;
        RECT 96.450 81.500 99.550 81.700 ;
        RECT 96.450 81.300 97.050 81.500 ;
        RECT 100.150 81.300 100.750 81.900 ;
        RECT 23.850 80.000 24.050 81.300 ;
        RECT 23.850 79.800 24.850 80.000 ;
        RECT 24.650 76.200 24.850 79.800 ;
        RECT 27.550 79.900 27.750 81.300 ;
        RECT 32.450 80.000 32.650 81.300 ;
        RECT 27.550 79.700 28.550 79.900 ;
        RECT 32.450 79.800 33.450 80.000 ;
        RECT 25.050 76.800 25.550 76.900 ;
        RECT 25.050 76.700 27.750 76.800 ;
        RECT 25.050 76.500 27.950 76.700 ;
        RECT 25.050 76.400 25.550 76.500 ;
        RECT 24.450 75.600 25.050 76.200 ;
        RECT 27.350 76.100 27.950 76.500 ;
        RECT 28.350 76.200 28.550 79.700 ;
        RECT 33.250 76.200 33.450 79.800 ;
        RECT 36.150 79.900 36.350 81.300 ;
        RECT 43.150 80.000 43.350 81.300 ;
        RECT 36.150 79.700 37.150 79.900 ;
        RECT 43.150 79.800 44.150 80.000 ;
        RECT 33.650 76.800 34.150 76.900 ;
        RECT 33.650 76.700 36.350 76.800 ;
        RECT 33.650 76.500 36.550 76.700 ;
        RECT 33.650 76.400 34.150 76.500 ;
        RECT 28.150 75.600 28.750 76.200 ;
        RECT 33.050 75.600 33.650 76.200 ;
        RECT 35.950 76.100 36.550 76.500 ;
        RECT 36.950 76.200 37.150 79.700 ;
        RECT 37.650 78.500 40.050 79.600 ;
        RECT 43.950 76.200 44.150 79.800 ;
        RECT 46.850 79.900 47.050 81.300 ;
        RECT 53.850 80.000 54.050 81.300 ;
        RECT 46.850 79.700 47.850 79.900 ;
        RECT 53.850 79.800 54.850 80.000 ;
        RECT 44.350 76.800 44.850 76.900 ;
        RECT 44.350 76.700 47.050 76.800 ;
        RECT 44.350 76.500 47.250 76.700 ;
        RECT 44.350 76.400 44.850 76.500 ;
        RECT 36.750 75.600 37.350 76.200 ;
        RECT 43.750 75.600 44.350 76.200 ;
        RECT 46.650 76.100 47.250 76.500 ;
        RECT 47.650 76.200 47.850 79.700 ;
        RECT 48.350 78.500 50.750 79.600 ;
        RECT 54.650 76.200 54.850 79.800 ;
        RECT 57.550 79.900 57.750 81.300 ;
        RECT 64.550 80.000 64.750 81.300 ;
        RECT 57.550 79.700 58.550 79.900 ;
        RECT 64.550 79.800 65.550 80.000 ;
        RECT 55.050 76.800 55.550 76.900 ;
        RECT 55.050 76.700 57.750 76.800 ;
        RECT 55.050 76.500 57.950 76.700 ;
        RECT 55.050 76.400 55.550 76.500 ;
        RECT 47.450 75.600 48.050 76.200 ;
        RECT 54.450 75.600 55.050 76.200 ;
        RECT 57.350 76.100 57.950 76.500 ;
        RECT 58.350 76.200 58.550 79.700 ;
        RECT 59.050 78.500 61.450 79.600 ;
        RECT 65.350 76.200 65.550 79.800 ;
        RECT 68.250 79.900 68.450 81.300 ;
        RECT 75.250 80.000 75.450 81.300 ;
        RECT 68.250 79.700 69.250 79.900 ;
        RECT 75.250 79.800 76.250 80.000 ;
        RECT 65.750 76.800 66.250 76.900 ;
        RECT 65.750 76.700 68.450 76.800 ;
        RECT 65.750 76.500 68.650 76.700 ;
        RECT 65.750 76.400 66.250 76.500 ;
        RECT 58.150 75.600 58.750 76.200 ;
        RECT 65.150 75.600 65.750 76.200 ;
        RECT 68.050 76.100 68.650 76.500 ;
        RECT 69.050 76.200 69.250 79.700 ;
        RECT 69.750 78.500 72.150 79.600 ;
        RECT 76.050 76.200 76.250 79.800 ;
        RECT 78.950 79.900 79.150 81.300 ;
        RECT 85.950 80.000 86.150 81.300 ;
        RECT 78.950 79.700 79.950 79.900 ;
        RECT 85.950 79.800 86.950 80.000 ;
        RECT 76.450 76.800 76.950 76.900 ;
        RECT 76.450 76.700 79.150 76.800 ;
        RECT 76.450 76.500 79.350 76.700 ;
        RECT 76.450 76.400 76.950 76.500 ;
        RECT 68.850 75.600 69.450 76.200 ;
        RECT 75.850 75.600 76.450 76.200 ;
        RECT 78.750 76.100 79.350 76.500 ;
        RECT 79.750 76.200 79.950 79.700 ;
        RECT 80.450 78.500 82.850 79.600 ;
        RECT 86.750 76.200 86.950 79.800 ;
        RECT 89.650 79.900 89.850 81.300 ;
        RECT 96.650 80.000 96.850 81.300 ;
        RECT 89.650 79.700 90.650 79.900 ;
        RECT 96.650 79.800 97.650 80.000 ;
        RECT 87.150 76.800 87.650 76.900 ;
        RECT 87.150 76.700 89.850 76.800 ;
        RECT 87.150 76.500 90.050 76.700 ;
        RECT 87.150 76.400 87.650 76.500 ;
        RECT 79.550 75.600 80.150 76.200 ;
        RECT 86.550 75.600 87.150 76.200 ;
        RECT 89.450 76.100 90.050 76.500 ;
        RECT 90.450 76.200 90.650 79.700 ;
        RECT 91.150 78.500 93.550 79.600 ;
        RECT 97.450 76.200 97.650 79.800 ;
        RECT 100.350 79.900 100.550 81.300 ;
        RECT 100.350 79.700 101.350 79.900 ;
        RECT 97.850 76.800 98.350 76.900 ;
        RECT 97.850 76.700 100.550 76.800 ;
        RECT 97.850 76.500 100.750 76.700 ;
        RECT 97.850 76.400 98.350 76.500 ;
        RECT 90.250 75.600 90.850 76.200 ;
        RECT 97.250 75.600 97.850 76.200 ;
        RECT 100.150 76.100 100.750 76.500 ;
        RECT 101.150 76.200 101.350 79.700 ;
        RECT 100.950 75.600 101.550 76.200 ;
        RECT 24.650 74.300 24.850 75.600 ;
        RECT 33.250 74.300 33.450 75.600 ;
        RECT 43.950 74.300 44.150 75.600 ;
        RECT 54.650 74.300 54.850 75.600 ;
        RECT 65.350 74.300 65.550 75.600 ;
        RECT 76.050 74.300 76.250 75.600 ;
        RECT 86.750 74.300 86.950 75.600 ;
        RECT 97.450 74.300 97.650 75.600 ;
        RECT 22.050 74.100 24.850 74.300 ;
        RECT 30.650 74.100 33.450 74.300 ;
        RECT 41.350 74.100 44.150 74.300 ;
        RECT 52.050 74.100 54.850 74.300 ;
        RECT 62.750 74.100 65.550 74.300 ;
        RECT 73.450 74.100 76.250 74.300 ;
        RECT 84.150 74.100 86.950 74.300 ;
        RECT 94.850 74.100 97.650 74.300 ;
        RECT 17.150 71.800 19.800 73.000 ;
        RECT 22.050 69.600 22.250 74.100 ;
        RECT 30.650 69.600 30.850 74.100 ;
        RECT 37.450 71.800 39.750 73.000 ;
        RECT 41.350 69.600 41.550 74.100 ;
        RECT 48.050 71.800 50.350 73.000 ;
        RECT 52.050 69.600 52.250 74.100 ;
        RECT 58.950 71.800 61.250 73.000 ;
        RECT 62.750 69.600 62.950 74.100 ;
        RECT 69.350 71.800 71.650 73.000 ;
        RECT 73.450 69.600 73.650 74.100 ;
        RECT 79.950 71.800 82.250 73.000 ;
        RECT 84.150 69.600 84.350 74.100 ;
        RECT 90.750 71.800 93.050 73.000 ;
        RECT 94.850 69.600 95.050 74.100 ;
        RECT 21.850 69.000 22.450 69.600 ;
        RECT 20.050 68.700 20.650 68.900 ;
        RECT 22.750 68.700 23.350 69.100 ;
        RECT 20.050 68.500 23.350 68.700 ;
        RECT 26.450 68.500 27.050 69.100 ;
        RECT 30.450 69.000 31.050 69.600 ;
        RECT 31.350 68.700 31.950 69.100 ;
        RECT 28.950 68.500 31.950 68.700 ;
        RECT 35.050 68.500 35.650 69.100 ;
        RECT 41.150 69.000 41.750 69.600 ;
        RECT 42.050 68.700 42.650 69.100 ;
        RECT 39.950 68.500 42.650 68.700 ;
        RECT 45.750 68.500 46.350 69.100 ;
        RECT 51.850 69.000 52.450 69.600 ;
        RECT 52.750 68.700 53.350 69.100 ;
        RECT 50.650 68.500 53.350 68.700 ;
        RECT 56.450 68.500 57.050 69.100 ;
        RECT 62.550 69.000 63.150 69.600 ;
        RECT 63.450 68.700 64.050 69.100 ;
        RECT 61.350 68.500 64.050 68.700 ;
        RECT 67.150 68.500 67.750 69.100 ;
        RECT 73.250 69.000 73.850 69.600 ;
        RECT 74.150 68.700 74.750 69.100 ;
        RECT 72.050 68.500 74.750 68.700 ;
        RECT 77.850 68.500 78.450 69.100 ;
        RECT 83.950 69.000 84.550 69.600 ;
        RECT 84.850 68.700 85.450 69.100 ;
        RECT 82.750 68.500 85.450 68.700 ;
        RECT 88.550 68.500 89.150 69.100 ;
        RECT 94.650 69.000 95.250 69.600 ;
        RECT 95.550 68.700 96.150 69.100 ;
        RECT 93.450 68.500 96.150 68.700 ;
        RECT 99.250 68.500 99.850 69.100 ;
        RECT 20.050 68.300 20.650 68.500 ;
        RECT 21.250 66.900 21.450 68.500 ;
        RECT 28.950 66.900 29.150 68.500 ;
        RECT 39.950 66.900 40.150 68.500 ;
        RECT 50.650 66.900 50.850 68.500 ;
        RECT 61.350 66.900 61.550 68.500 ;
        RECT 72.050 66.900 72.250 68.500 ;
        RECT 82.750 66.900 82.950 68.500 ;
        RECT 93.450 66.900 93.650 68.500 ;
        RECT 21.250 66.700 93.650 66.900 ;
        RECT 29.750 65.300 32.150 66.400 ;
        RECT 38.550 65.300 40.950 66.400 ;
        RECT 49.150 65.300 51.550 66.400 ;
        RECT 59.850 65.300 62.250 66.400 ;
        RECT 71.050 65.300 73.450 66.400 ;
        RECT 81.550 65.300 83.950 66.400 ;
        RECT 92.350 65.300 94.750 66.400 ;
      LAYER met3 ;
        RECT 1.000 98.150 35.300 99.550 ;
        RECT 41.050 98.200 43.350 99.400 ;
        RECT 52.750 98.200 55.050 99.400 ;
        RECT 62.150 98.200 64.450 99.400 ;
        RECT 73.950 98.200 76.250 99.400 ;
        RECT 84.450 98.200 86.750 99.400 ;
        RECT 37.750 94.500 40.050 94.600 ;
        RECT 37.750 93.400 40.150 94.500 ;
        RECT 48.450 93.400 50.850 94.500 ;
        RECT 59.150 93.400 61.550 94.500 ;
        RECT 69.850 93.400 72.250 94.500 ;
        RECT 80.550 93.400 82.950 94.500 ;
        RECT 91.250 93.400 93.650 94.500 ;
        RECT 24.850 89.900 25.450 90.500 ;
        RECT 33.450 89.900 34.050 90.500 ;
        RECT 44.150 89.900 44.750 90.500 ;
        RECT 54.850 89.900 55.450 90.500 ;
        RECT 65.550 89.900 66.150 90.500 ;
        RECT 76.250 89.900 76.850 90.500 ;
        RECT 86.950 89.900 87.550 90.500 ;
        RECT 97.650 89.900 98.250 90.500 ;
        RECT 1.000 84.950 22.350 86.200 ;
        RECT 1.050 71.800 19.850 73.000 ;
        RECT 25.050 68.900 25.350 89.900 ;
        RECT 26.450 68.900 27.050 69.100 ;
        RECT 25.050 68.600 27.050 68.900 ;
        RECT 33.650 68.900 33.950 89.900 ;
        RECT 38.050 85.000 40.350 86.200 ;
        RECT 37.650 79.600 39.950 79.700 ;
        RECT 37.650 78.500 40.050 79.600 ;
        RECT 37.450 71.800 39.750 73.000 ;
        RECT 35.050 68.900 35.650 69.100 ;
        RECT 33.650 68.600 35.650 68.900 ;
        RECT 44.350 68.900 44.650 89.900 ;
        RECT 48.750 85.000 51.050 86.200 ;
        RECT 48.350 78.500 50.750 79.600 ;
        RECT 48.050 71.800 50.350 73.000 ;
        RECT 45.750 68.900 46.350 69.100 ;
        RECT 44.350 68.600 46.350 68.900 ;
        RECT 55.050 68.900 55.350 89.900 ;
        RECT 59.450 85.000 61.750 86.200 ;
        RECT 59.050 78.500 61.450 79.600 ;
        RECT 58.950 71.800 61.250 73.000 ;
        RECT 56.450 68.900 57.050 69.100 ;
        RECT 55.050 68.600 57.050 68.900 ;
        RECT 65.750 68.900 66.050 89.900 ;
        RECT 70.150 85.000 72.450 86.200 ;
        RECT 69.750 78.500 72.150 79.600 ;
        RECT 69.350 71.800 71.650 73.000 ;
        RECT 67.150 68.900 67.750 69.100 ;
        RECT 65.750 68.600 67.750 68.900 ;
        RECT 76.450 68.900 76.750 89.900 ;
        RECT 80.850 85.000 83.150 86.200 ;
        RECT 80.450 78.500 82.850 79.600 ;
        RECT 79.950 71.800 82.250 73.000 ;
        RECT 77.850 68.900 78.450 69.100 ;
        RECT 76.450 68.600 78.450 68.900 ;
        RECT 87.150 68.900 87.450 89.900 ;
        RECT 91.550 85.000 93.850 86.200 ;
        RECT 91.150 79.600 93.450 79.700 ;
        RECT 91.150 78.500 93.550 79.600 ;
        RECT 90.750 71.800 93.050 73.000 ;
        RECT 88.550 68.900 89.150 69.100 ;
        RECT 87.150 68.600 89.150 68.900 ;
        RECT 97.850 68.900 98.150 89.900 ;
        RECT 99.250 68.900 99.850 69.100 ;
        RECT 97.850 68.600 99.850 68.900 ;
        RECT 26.450 68.500 27.050 68.600 ;
        RECT 35.050 68.500 35.650 68.600 ;
        RECT 45.750 68.500 46.350 68.600 ;
        RECT 56.450 68.500 57.050 68.600 ;
        RECT 67.150 68.500 67.750 68.600 ;
        RECT 77.850 68.500 78.450 68.600 ;
        RECT 88.550 68.500 89.150 68.600 ;
        RECT 99.250 68.500 99.850 68.600 ;
        RECT 38.550 66.400 40.850 66.500 ;
        RECT 92.350 66.400 94.650 66.500 ;
        RECT 29.750 65.300 32.150 66.400 ;
        RECT 38.550 65.300 40.950 66.400 ;
        RECT 49.150 65.300 51.550 66.400 ;
        RECT 59.850 65.300 62.250 66.400 ;
        RECT 71.050 65.300 73.450 66.400 ;
        RECT 81.550 65.300 83.950 66.400 ;
        RECT 92.350 65.300 94.750 66.400 ;
      LAYER met4 ;
        RECT 6.000 93.500 40.150 94.500 ;
        RECT 6.000 93.400 38.050 93.500 ;
        RECT 6.000 78.050 40.300 80.100 ;
        RECT 6.000 65.350 32.150 66.400 ;
        RECT 6.000 65.300 30.050 65.350 ;
  END
END tt_um_irfantekin_analog
END LIBRARY

